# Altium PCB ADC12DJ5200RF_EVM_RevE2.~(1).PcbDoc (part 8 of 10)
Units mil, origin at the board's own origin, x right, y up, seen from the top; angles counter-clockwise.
Board outline 10500 x 2750 mil, 14 copper layers (Top Copper, Layer 2 (GND1), Layer 3 (SIG1), Layer 4 (GND2, Layer 5 (PWR1), Layer 6 (GND3), Layer 7 (PWR/SIGNAL2), Layer 8 (PWR/SIGNAL3), Layer 9 (GND4), Layer 10 PWR2), Layer 11 (GND5), Layer 12 (SIG4), Layer 13 (GND6), Bottom Copper), stack 60.6 mil thick; 701 components, 826 nets, 3386 pads, 2128 vias.

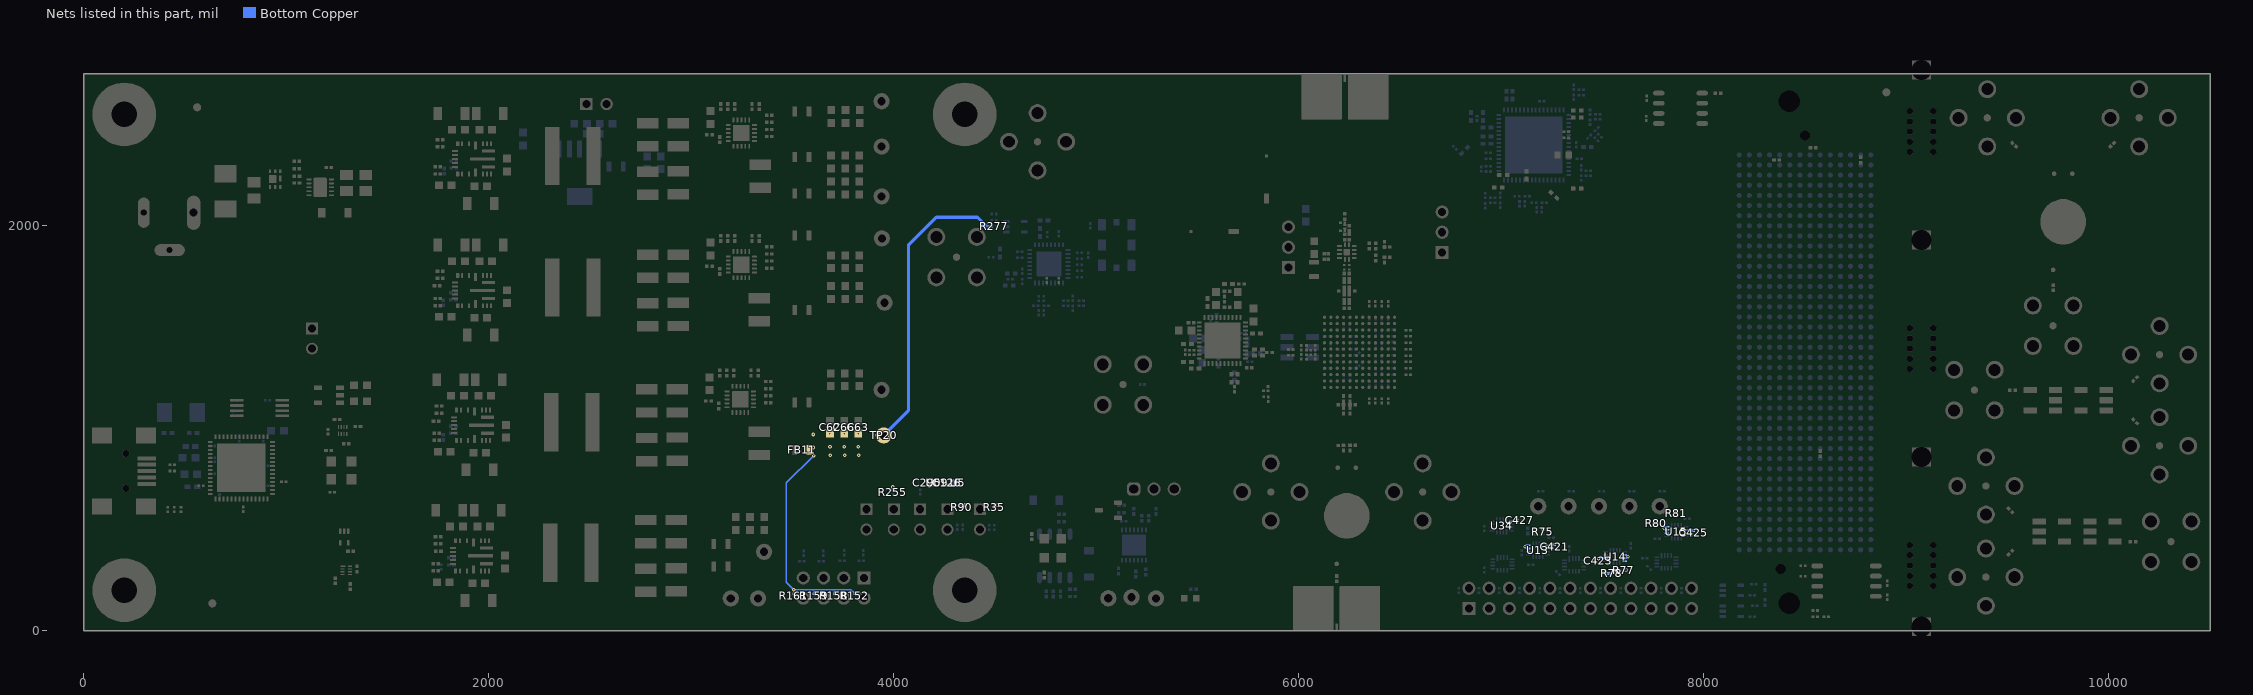
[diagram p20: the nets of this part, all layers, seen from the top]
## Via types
v1: diameter 18, hole 8, Top Copper to Bottom Copper, tented both sides, 1234 vias
v2: diameter 18, hole 8, Top Copper to Bottom Copper, tented top, 219 vias
v3: diameter 16, hole 8, Top Copper to Bottom Copper, tented both sides, 138 vias
v4: diameter 19.68, hole 7.87, Top Copper to Bottom Copper, 103 vias
v5: diameter 20, hole 10, Top Copper to Bottom Copper, tented top, 96 vias
v6: diameter 20, hole 10, Top Copper to Bottom Copper, tented both sides, 71 vias
v7: diameter 15.75/18/18/18/16/18/18/18/18/16/18/18/18/18 (per signal layer), hole 8, Top Copper to Bottom Copper, 50 vias
v8: diameter 20, hole 10, Top Copper to Bottom Copper, 40 vias
v9: diameter 15.75, hole 7.87, Top Copper to Bottom Copper, 28 vias
v10: diameter 21.81, hole 10, Top Copper to Bottom Copper, 26 vias
v11: diameter 15.75/16/16/16/16/16/16/16/16/16/16/16/16/18 (per signal layer), hole 8, Top Copper to Bottom Copper, 26 vias
v12: diameter 18, hole 8, Top Copper to Bottom Copper, tented bottom, 18 vias
v13: diameter 25.75, hole 15.75, Top Copper to Bottom Copper, 16 vias
v14: diameter 15.75/16/16/16/16/16/16/18/16/16/16/16/16/18 (per signal layer), hole 8, Top Copper to Bottom Copper, 15 vias
v15: diameter 30, hole 15, Top Copper to Bottom Copper, tented both sides, 12 vias
v16: diameter 15.75/16/16/16/18/16/16/16/16/16/16/16/16/18 (per signal layer), hole 8, Top Copper to Bottom Copper, 11 vias
v17: diameter 15.75/16/16/16/16/16/16/16/16/18/16/16/16/18 (per signal layer), hole 8, Top Copper to Bottom Copper, 7 vias
v18: diameter 15.75/16/16/16/16/16/16/18/16/18/16/16/16/18 (per signal layer), hole 8, Top Copper to Bottom Copper, 5 vias
v19: diameter 119.29, hole 77.95, Top Copper to Bottom Copper, 4 vias
v20: diameter 18, hole 8, Top Copper to Bottom Copper, 4 vias
v21: diameter 15.75/16/16/16/18/16/16/18/16/16/16/16/16/18 (per signal layer), hole 8, Top Copper to Bottom Copper, 2 vias
v22: diameter 15.75/16/16/16/16/16/18/16/16/16/16/16/16/18 (per signal layer), hole 8, Top Copper to Bottom Copper, 2 vias
v23: diameter 15.75/16/16/16/16/16/18/18/16/16/16/16/16/18 (per signal layer), hole 8, Top Copper to Bottom Copper, 1 vias

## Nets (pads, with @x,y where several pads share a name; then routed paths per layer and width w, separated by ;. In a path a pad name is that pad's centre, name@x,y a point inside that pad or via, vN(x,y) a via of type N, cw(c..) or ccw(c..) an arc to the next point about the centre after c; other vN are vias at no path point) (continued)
VDDL19: C62.1 C63.1 C66.1 C126.1 C290.1 C421.1 C423.1 C425.1 C427.1 FB11.2 R35.1 R75.1 R77.1 R78.1 R80.1 R81.1 R90.1 R152.2 R158.2 R159.2 R161.2 R255.2 R277.2 TP20.1 U5.1 U5.6 U13.5 U13.14 U13.15 U13.16 U14.6 U14.14 U14.15 U14.16 U15.6 U15.14 U15.15 U15.16 U34.13 U59.6 | length 2974.5
  Bottom Copper w7: R161.2@3506,183.05 v1(3506,203) ; v1(3605,865) 3470,730 3470,239 v1(3506,203) ; R159.2@3606,183.05 3606,202 3605,203 ; R158.2@3706,183.05 3706,202 3707,203 ; R152.2@3807,184.05 3788.05,203 3707,203 ; v3(7480,356.02) 7482.6,358.62 U14.6@7514.88,358.62 ; v3(7513,291) 7521,283 R78.1@7532.01,283 ; v1(3506,203) 3605,203 ; 3605,203 3707,203
  Bottom Copper w8: v3(7068,542) 7071,545 C427.1@7078.98,545 ; U13.14@7133.5,390.47 U13.15@7133.5,406.22 7125.78,406.22 v3(7117,415) 7123.97,421.97 U13.16@7133.5,421.97 ; v3(7246,422) 7250.02,426.02 C421.1@7265,426.02 ; U14.16@7609.37,342.87 U14.15@7609.37,358.62 7618.62,358.62 v3(7626,366) 7617.63,374.37 U14.14@7609.37,374.37 ; U15.14@7817.76,482.13 U15.15@7817.76,497.87 7812.13,497.87 v3(7805,505) 7813.62,513.62 U15.16@7817.76,513.62 ; U15.6@7912.24,497.87 7929.87,497.87 v3@7931.72,496.02
  Bottom Copper w10: v3@7931.72,496.02 C425.1@7950,496.02
  Bottom Copper w11.5: R255.2@3995,696.02 v1(3995,710) ; v1(4176,717) 4177.19,718.19 U59.6@4195.31,718.19 ; v1(4278,719) 4278.81,718.19 U5.6@4295.31,718.19 U5.1@4295.31,740.83 ; R90.1@4335,621.02 v1(4353,621) ; 4456.81,1998.19 R277.2@4483.98,1998.19 ; R35.1@4496.02,621.02 v20(4511,621)
  Bottom Copper w15: TP20.1@3950,965 4072,1087 4072,1904.02 4209.98,2042 4413,2042 4456.81,1998.19
  other v1: 3687.09,866.5 3757.09,866.5 3827.09,866.5 3603,905 3684.76,909.05 3754.76,909.05 3824.76,909.05 3602.91,969.57 3684.68,973.61 3754.68,973.61 3824.68,973.61
  other v3: 7616.02,300 7930,498 7205.98,499.41 7753.98,530 7865,591.02
pads on no net: FID1.1 FID2.1 FID3.1 FID4.1 FID5.1 FID6.1 J1. J20.10 J20.11 LBL1.0 Q2.0 Q2.0_1 U7.4A U7.4B U7.8A U7.8B U7.9A U7.9B U7.9C U7.9D U7.10A U7.10B U7.14A U7.14B U9.4A U9.4B U9.8A U9.8B U9.9A U9.9B U9.9C U9.9D U9.10A U9.10B U9.14A U9.14B U17. U23.4A U23.4B U23.8A U23.8B U23.9A U23.9B U23.9C U23.9D U23.10A U23.10B U23.14A U23.14B U43.4A U43.4B U43.8A U43.8B U43.9A U43.9B U43.9C U43.9D U43.10A U43.10B U43.14A U43.14B U51.1_1 U51.1_2 U51.2_1 U51.2_2 U51.3_1 U51.3_2 U51.4_1 U51.4_2 U51.5_1 U51.5_2 U51.6_1 U51.6_2 U52.41@5565.55,1375.9 U52.41@5565.55,1433.38 U52.41@5565.55,1490.86 U52.41@5623.03,1375.9 U52.41@5623.03,1433.38 U52.41@5623.03,1490.86 U52.41@5680.51,1375.9 U52.41@5680.51,1433.38 U52.41@5680.51,1490.86

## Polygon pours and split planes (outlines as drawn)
GND on Top Copper "GND_L01_P794" (solid, remove dead copper, pour order 794): 30,2720 8994,2720 8994,30 30,30
+3.6V on Top Copper "+3.6V_L01_P786" (solid, pour order 786): 2484,2241.09 2484,2486 2705,2486 2705,2439.4 3193,2439.4 3193,2419.79 3232,2419.79 3232,2240 2554,2240 2549,2241.09
GND on Top Copper "GND_L01_P792" (solid, pour order 792): 84 vertices, not listed, extent 1645,2037 3410,2665
GND on Top Copper "Top Copper-GND 2" (solid, pour order 755): 79 vertices, not listed, extent 6138.19,-40.71 6235.81,293.66
GND2 on Top Copper "Top Copper-GND2 17" (solid, pour order 728): 98 vertices, not listed, extent 6137.09,222.46 6236.91,380.03
GND2 on Top Copper "Top Copper-GND2 5" (solid, pour order 735): 110 vertices, not listed, extent 9489.92,1134.79 9683.69,1242.17
GND2 on Top Copper "Top Copper-GND2 6" (solid, pour order 750): 104 vertices, not listed, extent 9279.63,1131.68 9559.1,1245.28
GND2 on Top Copper "Top Copper-GND2 7" (solid, pour order 744): 105 vertices, not listed, extent 9336.33,208.2 9555.53,427.41
GND2 on Top Copper "Top Copper-GND2 8" (solid, pour order 743): 105 vertices, not listed, extent 9336.33,552.59 9555.53,771.8
GND2 on Top Copper "Top Copper-GND2 9" (solid, pour order 772): 288 vertices, not listed, extent 9467.2,426.02 9977.69,635.78
GND2 on Top Copper "Top Copper-GND2 10" (solid, pour order 770): 229 vertices, not listed, extent 9472.35,294.25 9977.69,493.69
GND2 on Top Copper "Top Copper-GND2 11" (solid, pour order 736): 110 vertices, not listed, extent 9960.31,386.31 10154.08,493.69
GND2 on Top Copper "Top Copper-GND2 12" (solid, pour order 749): 104 vertices, not listed, extent 10084.9,383.2 10364.37,496.8
GND2 on Top Copper "Top Copper-GND2 13" (solid, pour order 741): 105 vertices, not listed, extent 10088.47,856.68 10307.67,1075.89
GND2 on Top Copper "Top Copper-GND2 14" (solid, pour order 767): 196 vertices, not listed, extent 9666.31,992.71 10171.65,1142.17
GND2 on Top Copper "Top Copper-GND2 15" (solid, pour order 766): 163 vertices, not listed, extent 9666.31,1134.79 10171.65,1284.26
GND2 on Top Copper "Top Copper-GND2 16" (solid, pour order 742): 105 vertices, not listed, extent 10088.47,1201.08 10307.67,1420.28
GND2 on Top Copper "GND2_L01_P793" (solid, remove dead copper, pour order 793): 10500,2750 9157,2750 9157,0 10500,0
GND2 on Top Copper "Top Copper-GND 1" (solid, pour order 746): 102 vertices, not listed, extent 9670.5,145.41 9779.5,422.58
GND2 on Top Copper "Top Copper-GND2" (solid, pour order 748): 103 vertices, not listed, extent 9345.5,2358.45 9574.52,2587.47
GND2 on Top Copper "Top Copper-GND2 1" (solid, pour order 747): 103 vertices, not listed, extent 9975.48,2358.45 10204.5,2587.47
GND2 on Top Copper "Top Copper-GND2 2" (solid, pour order 756): 146 vertices, not listed, extent 9766.47,2205.95 10058.66,2441.63
GND2 on Top Copper "Top Copper-GND2 3" (solid, pour order 757): 147 vertices, not listed, extent 9491.34,2205.95 9783.53,2441.63
GND2 on Top Copper "Top Copper-GND2 4" (solid, pour order 745): 102 vertices, not listed, extent 9670.5,1451.41 9779.5,1728.58
no net on Top Copper "NONET_L01_P718" (solid, remove dead copper, pour order 718): 8994.2,2043.1
GND on Top Copper "Top Copper-GND 11" (solid, pour order 761): 79 vertices, not listed, extent 6190.52,2021.1 6263.94,2773.61
GND on Top Copper "Top Copper-GND" (solid, pour order 737): 106 vertices, not listed, extent 6201.62,2020.46 6296.53,2267.53
GND on Top Copper "Top Copper-GND 5" (solid, pour order 734): 122 vertices, not listed, extent 6204.19,753.03 6333.92,939.64
GND on Top Copper "Top Copper-GND 6" (solid, pour order 733): 126 vertices, not listed, extent 6140.08,753.03 6269.81,939.64
GND on Top Copper "Top Copper-GND 7" (solid, pour order 740): 41 vertices, not listed, extent 6171.4,866.21 6270.6,1122.61
GND on Top Copper "Top Copper-GND 8" (solid, pour order 739): 45 vertices, not listed, extent 6203.37,866.42 6302.58,1122.61
GND on Top Copper "Top Copper-GND 9" (solid, pour order 759): 135 vertices, not listed, extent 6229.36,628.48 6668.52,964.81
GND on Top Copper "Top Copper-GND 10" (solid, pour order 758): 133 vertices, not listed, extent 5805.48,628.48 6244.62,963.84
NetC94_1 on Top Copper "NETC94_1_L01_P724" (solid, remove dead copper, pour order 724): 6300,1850.93 6360,1850.93 6360,1839.93 6361,1840.93 6398,1840.93 6398,1831.93 6451,1831.93 6451,1884.93 6398,1884.93 6398,1881.93 6397,1881.93 6360,1881.93 6360,1868.93 6300,1868.93
GND on Top Copper "Top Copper-GND 3" (solid, pour order 725): 149 vertices, not listed, extent 6174.78,1501.67 6299.23,1594.79
VD11 on Top Copper "VD11_L01_P769" (solid, pour order 769): 3171,520 3380,520 3410,520 3425,505 3430,500 3430,380 3430,305 3413,288 3171.02,288
GND on Top Copper "GND_L01_P791" (solid, pour order 791): 86 vertices, not listed, extent 1645,1387 3410,2015
GND on Top Copper "GND_L01_P790" (solid, pour order 790): 88 vertices, not listed, extent 1640,722 3405,1350
GND on Top Copper "GND_L01_P789" (solid, pour order 789): 62 vertices, not listed, extent 1635,77 2981,705
+1.4V on Top Copper "+1.4V_L01_P787" (solid, pour order 787): 2484,1591.09 2484,1838 2705,1838 2705,1789.4 3193,1789.4 3193,1769.79 3232,1769.79 3232,1590 2554,1590 2549,1591.09
+2.2V on Top Copper "+2.2V_L01_P788" (solid, pour order 788): 2479,910.86 2479,1171 2701.73,1171 2701.73,1109.17 3229,1109.17 3229,909.77 2550.73,909.77 2545.73,910.86
NetC107_1 on Top Copper "NETC107_1_L01_P719" (solid, remove dead copper, pour order 719): 6232,1896
3p3VAMP on Top Copper "3P3VAMP_L01_P777" (solid, pour order 777): 4001.77,1830 4001.77,1980 3571,1980 3571,1830
NetC208_2 on Top Copper "NETC208_2_L01_P765" (solid, pour order 765): 27 vertices, not listed, extent 1902,2211 2304,2463
NetC129_2 on Top Copper "NETC129_2_L01_P762" (solid, pour order 762): 27 vertices, not listed, extent 1902,1561 2304,1813
NetC165_2 on Top Copper "NETC165_2_L01_P764" (solid, pour order 764): 27 vertices, not listed, extent 1897,896 2299,1148
NetC67_2 on Top Copper "NETC67_2_L01_P763" (solid, pour order 763): 27 vertices, not listed, extent 1892,251 2294,503
+7V on Top Copper "+7V_L01_P729" (solid, pour order 729): 1840,2150 1840,2072.6 1955,2072.6 1955,2285 1920,2285 1920,2222.27 1898.98,2222.27 1898.98,2150
+7V on Top Copper "+7V_L01_P732" (solid, pour order 732): 1840,1500 1840,1422.6 1955,1422.6 1955,1635 1920,1635 1920,1572.27 1898.98,1572.27 1898.98,1500
+7V on Top Copper "+7V_L01_P731" (solid, pour order 731): 1835,835 1835,757.6 1950,757.6 1950,970 1915,970 1915,907.27 1893.98,907.27 1893.98,835
+7V on Top Copper "+7V_L01_P730" (solid, pour order 730): 1830,190 1830,112.6 1945,112.6 1945,325 1910,325 1910,262.27 1888.98,262.27 1888.98,190
+7V on Top Copper "+7V_L01_P751" (solid, pour order 751): 18 vertices, not listed, extent 1835,2375 1980,2625
+7V on Top Copper "+7V_L01_P752" (solid, pour order 752): 18 vertices, not listed, extent 1835,1725 1980,1975
+7V on Top Copper "+7V_L01_P754" (solid, pour order 754): 18 vertices, not listed, extent 1830,1060 1975,1310
+7V on Top Copper "+7V_L01_P753" (solid, pour order 753): 18 vertices, not listed, extent 1825,415 1970,665
GND on Top Copper "GND_L01_P717" (solid, remove dead copper, pour order 717): 5942.85,933.69
VA11 on Top Copper "VA11_L01_P776" (solid, pour order 776): 4000,1510 4000,1660 3571,1660 3571,1510
NetC164_1 on Top Copper "NETC164_1_L01_P760" (solid, pour order 760): 3390,1840 3429.19,1840 3438.19,1831 3521,1831 3521,1559 3430,1559 3430,1625 3265,1625 3265,1760 3295,1760 3295,1771.58 3390,1771.58
+3.3VCLK on Top Copper "+3.3VCLK_L01_P774" (solid, pour order 774): 3571,2690 3571,2540 3995,2540 3995,2690
VA19 on Top Copper "VA19_L01_P768" (solid, pour order 768): 3993.66,1100 3993.66,1240 3571,1240 3571,1100
VDDD33 on Top Copper "VDDD33_L01_P775" (solid, pour order 775): 3571,2465 3571,2315 3995,2315 3995,2465
VDDL19 on Top Copper "VDDL19_L01_P771" (solid, pour order 771): 3991.77,855 3991.77,1005 3571,1005 3571,855
3.3V-LMX on Top Copper "3.3V-LMX_L01_P778" (solid, pour order 778): 4001.77,2035 4001.77,2185 3571,2185 3571,2035
NetC101_1 on Top Copper "NETC101_1_L01_P783" (solid, pour order 783): 2544,280 3121,280 3121,479.4 2695,479.4 2695,529 2476,529 2476,281.09 2539,281.09
NetC7_1 on Top Copper "NETC7_1_L01_P781" (solid, pour order 781): 19 vertices, not listed, extent 3265,1928.02 3521,2688.02
NetC200_1 on Top Copper "NETC200_1_L01_P773" (solid, pour order 773): 3425,910 3425,869 3521,869 3521,1260 3433.19,1260 3433.19,1175 3385,1175 3385,1106.58 3290,1106.58 3290,1095 3260,1095 3260,960 3425,960
NetC310_1 on Top Copper "NETC310_1_L01_P780" (solid, pour order 780): 27 vertices, not listed, extent 4684,1661 5002,2011
GND on Top Copper "GND_L01_P727" (solid, pour order 727): 17 vertices, not listed, extent 4704,1734 4828,1826
NetC55_2 on Top Copper "NETC55_2_L01_P726" (solid, pour order 726): 20 vertices, not listed, extent 6985.12,2170.15 7160,2244
NetC235_2 on Top Copper "NETC235_2_L01_P784" (solid, pour order 784): 239,1969 397,1969 397,2123 397,2190 871,2190 909,2190 909,2184 909,2182 949,2182 952,2182 952,2202 952,2356 654,2356 239,2356 239,2284
NetC116_2 on Top Copper "NETC116_2_L01_P722" (solid, pour order 722): 1845,305 1845,277.52 1836.02,268.54 1834.98,267.5 1834.98,245 1834.98,229.98 1825,220 1785,220 1785,270 1825,310 1840,310
NetC193_2 on Top Copper "NETC193_2_L01_P723" (solid, pour order 723): 1850,950 1850,922.52 1841.02,913.54 1839.98,912.5 1839.98,890 1839.98,874.98 1830,865 1790,865 1790,915 1830,955 1845,955
NetC137_2 on Top Copper "NETC137_2_L01_P721" (solid, pour order 721): 1855,1615 1855,1587.52 1846.02,1578.54 1844.98,1577.5 1844.98,1555 1844.98,1539.98 1835,1530 1795,1530 1795,1580 1835,1620 1850,1620
NetC235_1 on Top Copper "NETC235_1_L01_P785" (solid, pour order 785): 20 vertices, not listed, extent 495,1929.75 1125,2226.5
+7V on Top Copper "+7V_L01_P782" (solid, pour order 782): 1212.31,2196 1600,2196 1600,2106.59 1600,1920 1343.29,1920 1211,1920 1211,2151.94
GND on Top Copper "GND_L01_P779" (solid, pour order 779): 19 vertices, not listed, extent 1135,2035 1485,2405
GND on Top Copper "GND_L01_P738" (solid, pour order 738): 1970,2300 2050,2300 2050,2295 2050,2045 2045,2045 1975,2045 1975,2055 1975,2045 1970,2045 1970,2220 1970,2240 1965,2240 1965,2280 1965,2300
NetC221_2 on Top Copper "NETC221_2_L01_P720" (solid, pour order 720): 1855,2265 1855,2237.52 1846.02,2228.54 1844.98,2227.5 1844.98,2205 1844.98,2189.98 1835,2180 1795,2180 1795,2230 1835,2270 1850,2270
GND on Bottom Copper "GND_L14_P846" (solid, remove dead copper, pour order 846): 30,2720 8970,2720 8970,30 30,30
FE_VDD on Bottom Copper "Bottom Copper-FE_VDD" (solid, remove dead copper, pour order 841): 2654.64,2268.42 2736,2268.42 2736,2318.02 3212,2318.02 3212,2373.02 2734.98,2373.02 2654.64,2373.02
+7V on Bottom Copper "Bottom Copper-+7V" (solid, remove dead copper, pour order 842): 2144.01,2228.02 2324.01,2228.02 2336,2228.02 2336,2339.67 2409,2339.67 2409,2421 2144.01,2421
NetFB4_1 on Bottom Copper "NETFB4_1_L14_P839" (solid, remove dead copper, pour order 839): 2486.19,2418.33 2509.81,2418.33 2509.81,2317.81 2509.04,2317.04 2604.8,2317.04 2604.8,2269.01 2604.8,2269 2486,2269
GND2 on Bottom Copper "GND2_L14_P845" (solid, remove dead copper, pour order 845): 10500,2750 9157,2750 9157,0 10500,0
GND on Bottom Copper "GND_L14_P844" (solid, remove dead copper, pour order 844): 5346.14,1971.69 5558.27,1759.56 5982.54,2183.82 5982.54,2325.24 5841.12,2466.66
NetC58_1 on Bottom Copper "NETC58_1_L14_P840" (solid, pour order 840): 6830,2499 6830,2430.07 6883.07,2377 6922,2377 6923,2378 6925.84,2380.84 6925.84,2534.65 6923.49,2537 6834.28,2537 6834.16,2536.87 6830,2532.72
NetC235_1 on Bottom Copper "NETC235_1_L14_P843" (solid, pour order 843): 509,2160 509,2161 1039,2161 1121,2161 1121,1953 1121,1884.61 558,1884.61 540,1884.61 540,1930 540,1945 487,1945 487,2057 487,2113 487,2160
VDDD33 on Layer 5 (PWR1) "VDDD33_L05_P812" (solid, remove dead copper, pour order 812): 40,2710 40,40 2680,40 2680,2020 6304,2020 6304,1650 7850,1650 7850,740 7040,740 6780,480 6780,40 8960,40 8960,2710
VD11 on Layer 5 (PWR1) "VD11_L05_P811" (solid, remove dead copper, pour order 811): 2720,40 6740,40 6740,500 7010,780 7810,780 7810,1620 6301,1620 6301,1020 2720,1020
GND2 on Layer 5 (PWR1) "GND2_L05_P810" (solid, remove dead copper, pour order 810): 10500,2750 9157,2750 9157,0 10500,0
VA11 on Layer 5 (PWR1) "VA11_L05_P809" (solid, remove dead copper, pour order 809): 6270,1060 2720,1060 2720,1980 6270,1980
+3.3VA on Layer 3 (SIG1) "+3.3VA_L03_P805" (solid, remove dead copper, pour order 805): 30,30 30,2720 3540,2720 3540,2320 3540,30
GND on Layer 3 (SIG1) "GND_L03_P806" (solid, remove dead copper, pour order 806): 3590,2720 3590,30 8970,30 8970,2720
GND2 on Layer 3 (SIG1) "GND2_L03_P804" (solid, remove dead copper, pour order 804): 10500,2750 9157,2750 9157,0 10500,0
NetC317_1 on Layer 3 (SIG1) "NETC317_1_L03_P803" (solid, pour order 803): 21 vertices, not listed, extent 4568,1661 5008,1943
+7V on Layer 7 (PWR/SIGNAL2) "+7V_L07_P801" (solid, remove dead copper, pour order 801): 40,2710 3480,2710 3480,1980 3480,960 3240,960 2980,960 2980,280 2980,40 40,40
GND on Layer 7 (PWR/SIGNAL2) "GND_L07_P802" (solid, remove dead copper, pour order 802): 8200,2710 8970,2710 8970,40 3040,40 3040,680 3040,920 3280,920 3520,920 3520,1080 3520,1620 4420,1620 5160,1620 8200,1620 8200,2100
+3.3VCLK on Layer 7 (PWR/SIGNAL2) "+3.3VCLK_L07_P800" (solid, remove dead copper, pour order 800): 3520,2710 3520,1660 8160,1660 8160,2710
GND2 on Layer 7 (PWR/SIGNAL2) "GND2_L07_P799" (solid, remove dead copper, pour order 799): 10500,2750 9157,2750 9157,0 10500,0
GND on Layer 7 (PWR/SIGNAL2) "GND_L07_P798" (solid, remove dead copper, pour order 798): 5346.14,1971.69 5558.27,1759.56 5982.54,2183.82 5982.54,2325.24 5841.12,2466.66
VDD18-USB on Layer 7 (PWR/SIGNAL2) "VDD18-USB_L07_P797" (solid, remove dead copper, pour order 797): 550,1025 1025,1025 1025,600 550,600
+7V on Layer 10 PWR2) "+7V_L10_P829" (solid, pour order 829): 40,2710 3480,2710 3480,40 40,40
VDDL19 on Layer 10 PWR2) "VDDL19_L10_P826" (solid, pour order 826): 3550,1060 4760,1060 4760,710 8060,710 8060,40 3550,40
3p3VAMP on Layer 10 PWR2) "3P3VAMP_L10_P825" (solid, remove dead copper, pour order 825): 3547,2720 3547,1797 6838,1797 6838,2720
GND2 on Layer 10 PWR2) "GND2_L10_P827" (solid, remove dead copper, pour order 827): 10500,2750 9157,2750 9157,0 10500,0
VA19 on Layer 10 PWR2) "VA19_L10_P824" (solid, remove dead copper, pour order 824): 4800,1100 4800,750 6840,750 6840,1414.95 6840,1740 3550.9,1740 3550.9,1414.95 3550,1414.95 3550,1100 3550.9,1100
GND on Layer 10 PWR2) "GND_L10_P828" (solid, pour order 828): 7540,1900 7540,2710 7750,2710 8970,2710 8970,40 8100,40 8100,750 6880,750 6880,1900
NetC47_1 on Layer 10 PWR2) "NETC47_1_L10_P823" (solid, pour order 823): 6880,2710 7500,2710 7500,1940 6880,1940
GND on Layer 8 (PWR/SIGNAL3) "GND_L08_P820" (solid, remove dead copper, pour order 820): 30,2720 8970,2720 8970,30 30,30
GND on Layer 8 (PWR/SIGNAL3) "GND_L08_P819" (solid, remove dead copper, pour order 819): 40,2710 4020,2710 4020,40 540,40 40,40 40,1720 380,1720 1200,1720 1200,1880 1200,2180 840,2180 40,2180
VDDD33 on Layer 8 (PWR/SIGNAL3) "VDDD33_L08_P817" (solid, remove dead copper, pour order 817): 4060,40 4060,570 5050,570 6790,570 6880,480 7320,480 7400,480 7440,440 7460,420 7460,300 7460,60 7440,40 6920,40
GND2 on Layer 8 (PWR/SIGNAL3) "GND2_L08_P818" (solid, remove dead copper, pour order 818): 10500,2750 9157,2750 9157,0 10500,0
NetC235_1 on Layer 8 (PWR/SIGNAL3) "NETC235_1_L08_P816" (solid, remove dead copper, pour order 816): 478.4,2159.14 479.69,2157.85 949.4,2157.85 1012.62,2157.85 1136.5,2033.97 1135.21,2032.68 1135.21,1908.8 1135.21,1882.99 1115.86,1863.64 1114.57,1862.35 655.19,1862.35 604.85,1862.35 496.46,1970.74 478.4,1988.8 478.4,2040.42
GND on Layer 12 (SIG4) "GND_L12_P836" (solid, pour order 836): 30,2718.69 8970,2718.69 8970,28.69 30,28.69
FE_VDD on Layer 12 (SIG4) "FE_VDD_L12_P833" (solid, pour order 833): 2890,2717.69 2890,2156.72 2895.85,2150.87 2906.91,2161.93 5940,2161.93 5940,1671.93 6750,1671.93 6750,2717.69 4512.85,2717.69
GND2 on Layer 12 (SIG4) "GND2_L12_P835" (solid, remove dead copper, pour order 835): 10500,2750 9157,2750 9157,0 10500,0
3.3V-LMX on Layer 12 (SIG4) "3.3V-LMX_L12_P834" (solid, pour order 834): 5803,2132 5921,2014 5921,1038 5605,722 3739,722 3581,880 3581,2085 3577,2089 3599,2118 3611,2130 3611,2132
no net on Layer 12 (SIG4) "NONET_L12_P832" (solid, remove dead copper, pour order 832): 2910,2721.93
no net on Layer 6 (GND3) "NONET_L06_P815" (solid, pour order 815): 30,2720 8860,2720 8970,2720 8970,30 30,30
GND on Layer 6 (GND3) "GND_L06_P814" (solid, pour order 814): 30,2720 8860,2720 8970,2720 8970,30 30,30
GND2 on Layer 6 (GND3) "GND2_L06_P813" (solid, remove dead copper, pour order 813): 10500,2750 9157,2750 9157,0 10500,0
GND on Layer 4 (GND2 "GND_L04_P808" (solid, remove dead copper, pour order 808): 30,2720 8970,2720 8970,30 30,30
GND2 on Layer 4 (GND2 "GND2_L04_P807" (solid, remove dead copper, pour order 807): 10500,2750 9157,2750 9157,0 10500,0
GND on Layer 9 (GND4) "GND_L09_P822" (solid, pour order 822): 8970,30 8970,2720 30,2720 30,30
GND2 on Layer 9 (GND4) "GND2_L09_P821" (solid, remove dead copper, pour order 821): 10500,2750 9157,2750 9157,0 10500,0
GND on Layer 11 (GND5) "GND_L11_P831" (solid, remove dead copper, pour order 831): 30,2720 8970,2720 8970,30 30,30
GND2 on Layer 11 (GND5) "GND2_L11_P830" (solid, remove dead copper, pour order 830): 10500,2750 9157,2750 9157,0 10500,0
GND on Layer 13 (GND6) "GND_L13_P838" (solid, pour order 838): 30,2720 8970,2720 8970,30 30,30
GND2 on Layer 13 (GND6) "GND2_L13_P837" (solid, remove dead copper, pour order 837): 10500,2750 9157,2750 9157,0 10500,0
GND on Layer 2 (GND1) "GND_L02_P796" (solid, remove dead copper, pour order 796): 30,2720 8993,2720 8993,30 30,30
GND2 on Layer 2 (GND1) "GND2_L02_P795" (solid, remove dead copper, pour order 795): 10500,2750 9157,2750 9157,0 10500,0

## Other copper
Top Copper:
  drawing of 126 lines, arcs and shapes, not listed
  text ".Layer_Name" at 576,-857 h60
Layer 2 (GND1):
  pour cut-out: 9802,2259.44 9802,2272.44 9838,2272.44 9838,2259.44 cw(c9820,2259.44) 9820,2241.44 cw(c9820,2259.44)
  pour cut-out: 9712,2259.44 9712,2272.44 9748,2272.44 9748,2259.44 cw(c9730,2259.44) 9730,2241.44 cw(c9730,2259.44)
  pour cut-out: 9743,1779.52 9743,1766.52 9707,1766.52 9707,1779.52 cw(c9725,1779.52) 9725,1797.52 cw(c9725,1779.52)
  pour cut-out: 10307.48,414 ccw(c10307.48,440) 10333.48,440 ccw(c10307.48,440) 10307.48,466 ccw(c10307.48,440) 10281.48,440 ccw(c10307.48,440)
  pour cut-out: 9393.13,689 ccw(c9393.13,715) 9419.13,715 ccw(c9393.13,715) 9393.13,741 ccw(c9393.13,715) 9367.13,715 ccw(c9393.13,715)
  pour cut-out: 9393.13,238.65 ccw(c9393.13,264.65) 9419.13,264.65 ccw(c9393.13,264.65) 9393.13,290.65 ccw(c9393.13,264.65) 9367.13,264.65 ccw(c9393.13,264.65)
  pour cut-out: 10124,2532.97 ccw(c10150,2532.97) 10150,2506.97 ccw(c10150,2532.97) 10176,2532.97 ccw(c10150,2532.97) 10150,2558.97 ccw(c10150,2532.97)
  pour cut-out: 9374,2532.97 ccw(c9400,2532.97) 9400,2506.97 ccw(c9400,2532.97) 9426,2532.97 ccw(c9400,2532.97) 9400,2558.97 ccw(c9400,2532.97)
  pour cut-out: 9699,1506 ccw(c9725,1506) 9725,1480 ccw(c9725,1506) 9751,1506 ccw(c9725,1506) 9725,1532 ccw(c9725,1506)
  pour cut-out: 10250.87,1389.83 ccw(c10250.87,1363.83) 10224.87,1363.83 ccw(c10250.87,1363.83) 10250.87,1337.83 ccw(c10250.87,1363.83) 10276.87,1363.83 ccw(c10250.87,1363.83)
  pour cut-out: 10250.87,939.48 ccw(c10250.87,913.48) 10224.87,913.48 ccw(c10250.87,913.48) 10250.87,887.48 ccw(c10250.87,913.48) 10276.87,913.48 ccw(c10250.87,913.48)
  pour cut-out: 9336.52,1214.48 ccw(c9336.52,1188.48) 9310.52,1188.48 ccw(c9336.52,1188.48) 9336.52,1162.48 ccw(c9336.52,1188.48) 9362.52,1188.48 ccw(c9336.52,1188.48)
  pour cut-out: 6205,327.58 6205,314.58 6169,314.58 6169,327.58 cw(c6187,327.58) 6187,345.58 cw(c6187,327.58)
  pour cut-out: 6174,807.5 6174,820.5 6210,820.5 6210,807.5 cw(c6192,807.5) 6192,789.5 cw(c6192,807.5)
  pour cut-out: 6264,807.5 6264,820.5 6300,820.5 6300,807.5 cw(c6282,807.5) 6282,789.5 cw(c6282,807.5)
  pour cut-out: 5836,685 ccw(c5862,685) 5862,659 ccw(c5862,685) 5888,685 ccw(c5862,685) 5862,711 ccw(c5862,685)
  pour cut-out: 6586,685 ccw(c6612,685) 6612,659 ccw(c6612,685) 6638,685 ccw(c6612,685) 6612,711 ccw(c6612,685)
  pour cut-out: 4992.97,1633.82 4992.97,1602.82 4993,1602.82 ccw(c5016,1603) 5038.98,1602.05 5038.99,1602.03 5038.99,1633.03 5038.96,1633.02 ccw(c5015.96,1632.86)
  pour cut-out: 7646.67,2469.24 7624.75,2447.32 7624.77,2447.3 ccw(c7641.16,2431.16) 7656.74,2414.24 7656.73,2414.21 7678.65,2436.14 7678.62,2436.15 ccw(c7662.24,2452.3)
  pour cut-out: 7515.35,2421.08 7493.43,2399.16 7493.45,2399.14 ccw(c7509.84,2383) 7525.41,2366.08 7525.4,2366.06 7547.33,2387.98 7547.3,2388 ccw(c7530.92,2404.15)
  pour cut-out: 6887.61,2265.5 6887.61,2296.5 6887.58,2296.49 ccw(c6864.58,2296.32) 6841.6,2297.27 6841.59,2297.29 6841.59,2266.29 6841.62,2266.29 ccw(c6864.62,2266.46)
  pour cut-out: 7171.21,1996.48 7202.21,1996.48 7202.2,1996.51 ccw(c7202.03,2019.51) 7202.98,2042.49 7203,2042.5 7172,2042.5 7172,2042.47 ccw(c7172.17,2019.47)
  pour cut-out: 4744.23,1540.65 4713.23,1540.65 4713.23,1540.62 ccw(c4713.41,1517.62) 4712.46,1494.64 4712.44,1494.63 4743.44,1494.63 4743.43,1494.66 ccw(c4743.27,1517.67)
  pour cut-out: 7525.54,2366.14 7547.46,2388.06 7547.44,2388.08 ccw(c7531.05,2404.22) 7515.47,2421.14 7515.48,2421.16 7493.56,2399.24 7493.58,2399.22 ccw(c7509.97,2383.07)
  pour cut-out: 7656.86,2414.3 7678.78,2436.22 7678.76,2436.23 ccw(c7662.37,2452.37) 7646.8,2469.3 7646.8,2469.32 7624.88,2447.4 7624.91,2447.38 ccw(c7641.29,2431.23)
  pour cut-out: 7466.4,2274.28 7466.4,2243.28 7466.43,2243.28 ccw(c7489.42,2243.46) 7512.41,2242.5 7512.41,2242.48 7512.41,2273.48 7512.39,2273.48 ccw(c7489.38,2273.31)
  pour cut-out: 7127.03,2644.75 7127.03,2675.75 7127,2675.74 ccw(c7104,2675.57) 7081.02,2676.52 7081.01,2676.54 7081.01,2645.54 7081.04,2645.54 ccw(c7104.04,2645.71)
  pour cut-out: 7436.16,2581.64 7467.16,2581.64 7467.16,2581.67 ccw(c7466.98,2604.67) 7467.93,2627.65 7467.95,2627.66 7436.95,2627.66 7436.96,2627.63 ccw(c7437.12,2604.63)
  pour cut-out: 7223.3,2622.8 7254.3,2622.8 7254.3,2622.83 ccw(c7254.12,2645.83) 7255.07,2668.81 7255.09,2668.82 7224.09,2668.82 7224.1,2668.79 ccw(c7224.26,2645.79)
  pour cut-out: 7086.61,1908.38 7117.61,1908.38 7117.61,1908.41 ccw(c7117.43,1931.41) 7118.39,1954.39 7118.41,1954.4 7087.41,1954.4 7087.41,1954.37 ccw(c7087.58,1931.37)
  pour cut-out: 5762.2,2254.55 ccw(c5840.92,2254.55) 5840.92,2175.83 ccw(c5840.92,2254.55) 5919.64,2254.55 ccw(c5840.92,2254.55) 5840.92,2333.27 ccw(c5840.92,2254.55)
  pour cut-out: 5558.25,1892.77 ccw(c5558.25,1971.49) 5636.97,1971.49 ccw(c5558.25,1971.49) 5558.25,2050.21 ccw(c5558.25,1971.49) 5479.53,1971.49 ccw(c5558.25,1971.49)
  pour cut-out: 6126.77,1475.22 ccw(c6126.77,1485.24) 6136.79,1485.24 ccw(c6126.77,1485.24) 6136.67,1486.77 6136.67,1515.2 ccw(c6126.77,1516.73) 6136.79,1516.73 ccw(c6126.77,1516.73) 6126.77,1526.75 ccw(c6126.77,1516.73) 6116.76,1516.73 ccw(c6126.77,1516.73) 6116.9,1515.05 6116.9,1486.91 ccw(c6126.77,1485.24) 6116.76,1485.24 ccw(c6126.77,1485.24)
  pour cut-out: 6126.77,1349.24 ccw(c6126.77,1359.25) 6136.79,1359.25 ccw(c6126.77,1359.25) 6136.67,1360.79 6136.67,1389.21 ccw(c6126.77,1390.75) 6136.79,1390.75 ccw(c6126.77,1390.75) 6126.77,1400.76 ccw(c6126.77,1390.75) 6116.76,1390.75 ccw(c6126.77,1390.75) 6116.9,1389.07 6116.9,1360.93 ccw(c6126.77,1359.25) 6116.76,1359.25 ccw(c6126.77,1359.25)
  pour cut-out: 6126.77,1223.25 ccw(c6126.77,1233.27) 6136.79,1233.27 ccw(c6126.77,1233.27) 6136.67,1234.8 6136.67,1263.23 ccw(c6126.77,1264.76) 6136.79,1264.76 ccw(c6126.77,1264.76) 6126.77,1274.78 ccw(c6126.77,1264.76) 6116.76,1264.76 ccw(c6126.77,1264.76) 6116.9,1263.09 6116.9,1234.95 ccw(c6126.77,1233.27) 6116.76,1233.27 ccw(c6126.77,1233.27)
  pour cut-out: 7699.03,2614.18 7699.03,2645.18 7699,2645.18 ccw(c7676,2645) 7653.02,2645.95 7653.01,2645.97 7653.01,2614.97 7653.04,2614.98 ccw(c7676.04,2615.14)
  pour cut-out: 6211.24,1201.77 ccw(c6221.26,1201.77) 6221.26,1191.76 ccw(c6221.26,1201.77) 6222.8,1191.88 6251.22,1191.88 ccw(c6252.76,1201.77) 6252.76,1191.76 ccw(c6252.76,1201.77) 6262.77,1201.77 ccw(c6252.76,1201.77) 6252.76,1211.79 ccw(c6252.76,1201.77) 6251.08,1211.64 6222.94,1211.64 ccw(c6221.26,1201.77) 6221.26,1211.79 ccw(c6221.26,1201.77)
  pour cut-out: 6211.24,1548.23 ccw(c6221.26,1548.23) 6221.26,1538.21 ccw(c6221.26,1548.23) 6222.8,1538.33 6251.22,1538.33 ccw(c6252.76,1548.23) 6252.76,1538.21 ccw(c6252.76,1548.23) 6262.77,1548.23 ccw(c6252.76,1548.23) 6252.76,1558.24 ccw(c6252.76,1548.23) 6251.08,1558.1 6222.94,1558.1 ccw(c6221.26,1548.23) 6221.26,1558.24 ccw(c6221.26,1548.23)
  pour cut-out: 6345,1535.9 6380,1535.9 6380.02,1535.88 ccw(c6377.76,1548.17) 6379.99,1560.47 6380,1560.5 6345,1560.5 6344.98,1560.52 ccw(c6347.24,1548.21)
  pour cut-out: 6407.99,1535.9 6442.99,1535.9 6443.01,1535.88 ccw(c6440.75,1548.17) 6442.99,1560.47 6442.99,1560.5 6407.99,1560.5 6407.97,1560.52 ccw(c6410.24,1548.21)
  pour cut-out: 6345,1189.44 6380,1189.44 6380.02,1189.42 ccw(c6377.76,1201.72) 6379.99,1214.01 6380,1214.04 6345,1214.04 6344.98,1214.06 ccw(c6347.24,1201.76)
  pour cut-out: 6407.99,1189.44 6442.99,1189.44 6443.01,1189.42 ccw(c6440.75,1201.72) 6442.99,1214.01 6442.99,1214.04 6407.99,1214.04 6407.97,1214.06 ccw(c6410.24,1201.76)
  pour cut-out: 6485.56,1451.5 6485.56,1486.5 6485.58,1486.52 ccw(c6473.28,1484.25) 6460.99,1486.49 6460.96,1486.5 6460.96,1451.5 6460.94,1451.47 ccw(c6473.24,1453.74)
  pour cut-out: 6485.56,1388.5 6485.56,1423.5 6485.58,1423.53 ccw(c6473.28,1421.26) 6460.99,1423.5 6460.96,1423.5 6460.96,1388.5 6460.94,1388.48 ccw(c6473.24,1390.75)
  pour cut-out: 6485.56,1325.51 6485.56,1360.51 6485.58,1360.53 ccw(c6473.28,1358.27) 6460.99,1360.51 6460.96,1360.51 6460.96,1325.51 6460.94,1325.49 ccw(c6473.24,1327.76)
  pour cut-out: 6485.56,1262.52 6485.56,1297.52 6485.58,1297.54 ccw(c6473.28,1295.28) 6460.99,1297.51 6460.96,1297.52 6460.96,1262.52 6460.94,1262.5 ccw(c6473.24,1264.76)
  pour cut-out: 9764.65,2269.34
  pour cut-out: 9505.12,587.07 9521.06,602.63 9504.2,619.87 9488.53,604.2
  pour cut-out: 9523.49,568.7 9539.43,584.25 9522.57,601.5 9506.9,585.82
  pour cut-out: 9539.43,395.37 9523.87,411.3 9506.63,394.45 9522.3,378.78
  pour cut-out: 9521.06,376.99 9505.5,392.93 9488.26,376.07 9503.93,360.4
  pour cut-out: 10120.7,451.27 10120.43,429 10144.54,428.73 10144.54,450.89
  pour cut-out: 10094.71,451.27 10094.44,429 10118.56,428.73 10118.56,450.89
  pour cut-out: 10069,420 10069,460 9994,460 9994,420
  pour cut-out: 9944,520 9944,560 9869,560 9869,520
  pour cut-out: 9944,420 9944,460 9869,460 9869,420
  pour cut-out: 9819,420 9819,460 9744,460 9744,420
  pour cut-out: 9694,520 9694,560 9619,560 9619,520
  pour cut-out: 9950,1108.48 9950,1068.48 10025,1068.48 10025,1108.48
  pour cut-out: 9825,1208.48 9825,1168.48 9900,1168.48 9900,1208.48
  pour cut-out: 9700,1208.48 9700,1168.48 9775,1168.48 9775,1208.48
  pour cut-out: 9700,1108.48 9700,1068.48 9775,1068.48 9775,1108.48
  pour cut-out: 9575,1208.48 9575,1168.48 9650,1168.48 9650,1208.48
  pour cut-out: 9549.29,1177.21 9549.56,1199.48 9525.44,1199.76 9525.44,1177.6
  pour cut-out: 9523.3,1177.21 9523.57,1199.48 9499.46,1199.76 9499.46,1177.6
  pour cut-out: 9736.27,1718.77 9714,1719.04 9713.73,1694.93 9735.89,1694.93
  pour cut-out: 9736.27,1692.79 9714,1693.06 9713.73,1668.94 9735.89,1668.94
  pour cut-out: 10024.19,2391.22 10008.63,2407.15 9991.39,2390.3 10007.06,2374.63
  pour cut-out: 10042.56,2409.59 10027,2425.53 10009.76,2408.67 10025.43,2393
  pour cut-out: 9524.11,2392.92 9540.05,2408.48 9523.19,2425.72 9507.52,2410.05
  pour cut-out: 9542.48,2374.55 9558.42,2390.1 9541.57,2407.35 9525.89,2391.68
  pour cut-out: 10122.94,1251.49 10138.5,1235.55 10155.74,1252.41 10140.07,1268.08
  pour cut-out: 10104.57,1233.12 10120.13,1217.18 10137.37,1234.04 10121.7,1249.71
  pour cut-out: 10120.51,1059.79 10104.57,1044.23 10121.43,1026.99 10137.1,1042.66
  pour cut-out: 10138.88,1041.41 10122.94,1025.86 10139.8,1008.61 10155.47,1024.29
  pour cut-out: 6218.4,1981.38 6236.08,1981.38 6236.1,1981.4 6236.1,1991.56 6236.08,1991.58 6218.4,1991.58
  pour cut-out: 6218.4,1998.7 6236.08,1998.7 6236.1,1998.72 6236.1,2008.88 6236.08,2008.9 6218.4,2008.9
  pour cut-out: 6219.1,1967.58 6235.28,1967.58 6235.3,1967.59 6235.3,1982.16 6235.28,1982.18 6219.1,1982.18
  pour cut-out: 6219.1,2007.9 6235.28,2007.9 6235.3,2007.92 6235.3,2022.48 6235.28,2022.5 6219.1,2022.5
  pour cut-out: 6238.5,2044.4 6216.23,2044.67 6215.96,2020.56 6238.12,2020.56
  pour cut-out: 6238.5,2070.39 6216.23,2070.66 6215.96,2046.54 6238.12,2046.54
  pour cut-out: 6256.92,1799.88 6241.12,1799.88 6241.11,1799.89 6241.11,1813.68 6241.12,1813.68 6256.9,1813.68 6256.91,1813.69
  pour cut-out: 6232.92,1799.88 6217.12,1799.88 6217.11,1799.89 6217.11,1813.68 6217.12,1813.68 6232.9,1813.68 6232.91,1813.69
  pour cut-out: 6256.92,1776.26 6241.12,1776.26 6241.11,1776.27 6241.11,1790.05 6241.12,1790.06 6256.9,1790.06 6256.91,1790.07
  pour cut-out: 6232.92,1776.26 6217.12,1776.26 6217.11,1776.27 6217.11,1790.05 6217.12,1790.06 6232.9,1790.06 6232.91,1790.07
  pour cut-out: 6258.11,1985.72 6235.84,1985.99 6235.57,1961.88 6257.73,1961.88
  pour cut-out: 6259.27,1968.2 6237,1968.47 6236.72,1944.36 6258.89,1944.36
  pour cut-out: 6259.27,1942.22 6237,1942.49 6236.72,1918.37 6258.89,1918.37
  pour cut-out: 6238.5,1969.28 6216.23,1969.55 6215.96,1945.44 6238.12,1945.44
  pour cut-out: 6238.5,1943.29 6216.23,1943.56 6215.96,1919.45 6238.12,1919.45
  pour cut-out: 6260.19,1775.78 6237.92,1776.05 6237.64,1751.94 6259.81,1751.94
  pour cut-out: 6260.19,1749.79 6237.92,1750.06 6237.64,1725.95 6259.81,1725.95
  pour cut-out: 6236.19,1775.78 6213.92,1776.05 6213.64,1751.94 6235.81,1751.94
  pour cut-out: 6236.19,1749.79 6213.92,1750.06 6213.64,1725.95 6235.81,1725.95
  pour cut-out: 6236.19,1732.77 6213.92,1733.04 6213.64,1708.93 6235.81,1708.93
  pour cut-out: 6236.19,1706.79 6213.92,1707.06 6213.64,1682.94 6235.81,1682.94
  pour cut-out: 6260.19,1732.77 6237.92,1733.04 6237.64,1708.93 6259.81,1708.93
  pour cut-out: 6260.19,1706.79 6237.92,1707.06 6237.64,1682.94 6259.81,1682.94
  pour cut-out: 6261.51,1666.71 6261.78,1688.98 6237.67,1689.26 6237.67,1667.1
  pour cut-out: 6212.35,1689.25 6212.08,1666.98 6236.19,1666.71 6236.19,1688.87
  pour cut-out: 6236.19,1672.77 6213.92,1673.04 6213.64,1648.93 6235.81,1648.93
  pour cut-out: 6236.19,1646.79 6213.92,1647.06 6213.64,1622.94 6235.81,1622.94
  pour cut-out: 6260.19,1672.77 6237.92,1673.04 6237.64,1648.93 6259.81,1648.93
  pour cut-out: 6260.19,1646.79 6237.92,1647.06 6237.64,1622.94 6259.81,1622.94
  pour cut-out: 6260.19,1629.78 6237.92,1630.05 6237.64,1605.94 6259.81,1605.94
  pour cut-out: 6260.19,1603.79 6237.92,1604.06 6237.64,1579.95 6259.81,1579.95
  pour cut-out: 6236.19,1629.78 6213.92,1630.05 6213.64,1605.94 6235.81,1605.94
  pour cut-out: 6236.19,1603.79 6213.92,1604.06 6213.64,1579.95 6235.81,1579.95
  pour cut-out: 6264.79,1104.73 6265.06,1127 6240.95,1127.27 6240.95,1105.11
  pour cut-out: 6232.78,1104.73 6233.05,1127 6208.94,1127.27 6208.94,1105.11
  pour cut-out: 6241.73,1121.22 6264,1120.95 6264.27,1145.06 6242.11,1145.06
  pour cut-out: 6241.73,1147.21 6264,1146.94 6264.27,1171.05 6242.11,1171.05
  pour cut-out: 6209.73,1121.22 6232,1120.95 6232.27,1145.06 6210.11,1145.06
  pour cut-out: 6209.73,1147.21 6232,1146.94 6232.27,1171.05 6210.11,1171.05
  pour cut-out: 6232.27,1110.78 6210,1111.05 6209.73,1086.94 6231.89,1086.94
  pour cut-out: 6232.27,1084.79 6210,1085.06 6209.73,1060.95 6231.89,1060.95
  pour cut-out: 6264.27,1110.78 6242,1111.05 6241.73,1086.94 6263.89,1086.94
  pour cut-out: 6264.27,1084.79 6242,1085.06 6241.73,1060.95 6263.89,1060.95
  pour cut-out: 6241.19,927.27 6240.92,905 6265.03,904.73 6265.03,926.89
  pour cut-out: 6267.17,927.27 6266.9,905 6291.02,904.73 6291.02,926.89
  pour cut-out: 6264.27,927.81 6242,928.08 6241.73,903.97 6263.89,903.97
  pour cut-out: 6264.27,901.83 6242,902.1 6241.73,877.98 6263.89,877.98
  pour cut-out: 6232.27,927.81 6210,928.08 6209.73,903.97 6231.89,903.97
  pour cut-out: 6232.27,901.83 6210,902.1 6209.73,877.98 6231.89,877.98
  pour cut-out: 6183.23,926.29 6182.96,904.02 6207.07,903.75 6207.07,925.91
  pour cut-out: 6209.21,926.29 6208.94,904.02 6233.06,903.75 6233.06,925.91
  pour cut-out: 6175.73,258.25 6198,257.98 6198.27,282.1 6176.11,282.1
  pour cut-out: 6175.73,232.27 6198,232 6198.27,256.11 6176.11,256.11
  pour cut-out: 6215.86,1923 6220,1893 6234,1893 6234,1923
  pour cut-out: 6258.14,1923 6254,1893 6240,1893 6240,1923
  pour cut-out: 6213.92,1802 6220.15,1847.18 6234.15,1847.18 6234.15,1802
  pour cut-out: 6260.38,1802 6254.15,1847.18 6240.15,1847.18 6240.15,1802
  pour cut-out: 6340,1712.1 6340,1675.8 6358,1675.8 6358,1712.1
  pour cut-out: 5708,1253.98 5708,1279 5686,1279 5686,1254.02
  pour cut-out: 5678,1253.98 5678,1279 5656,1279 5656,1254.02
  pour cut-out: 5768.98,1349 5794,1349 5794,1371 5769.02,1371
  pour cut-out: 5768.98,1378 5794,1378 5794,1400 5769.02,1400
  pour cut-out: 6047.99,1356 6084,1356 6084,1372 6048.01,1372
  pour cut-out: 6047.99,1378 6084,1378 6084,1394 6048.01,1394
  pour cut-out: 6026,1393.01 6026,1357 6042,1357 6042,1392.99
  pour cut-out: 6021.01,1369 5985,1369 5985,1351 6020.99,1351
  pour cut-out: 6021.01,1398 5985,1398 5985,1380 6020.99,1380
  pour cut-out: 5979.01,1398 5943,1398 5943,1380 5978.99,1380
  pour cut-out: 5979.01,1369 5943,1369 5943,1351 5978.99,1351
  pour cut-out: 7708.7,2529.05 7708.7,2508.85 7721.3,2508.85 7721.3,2529.05
  pour cut-out: 7708.7,2551.1 7708.7,2530.9 7721.3,2530.9 7721.3,2551.1
  pour cut-out: 7711.7,2628.05 7711.7,2607.85 7724.3,2607.85 7724.3,2628.05
  pour cut-out: 7711.7,2650.1 7711.7,2629.9 7724.3,2629.9 7724.3,2650.1
  pour cut-out: 6558.2,1476.7 6521.8,1476.7 6521.8,1493.3 6558.2,1493.3
  pour cut-out: 7749.01,2492.98 7749.01,2517.16 7806.32,2517.16 7806.32,2492.98
  pour cut-out: 7749.01,2542.98 7749.01,2567.16 7806.32,2567.16 7806.32,2542.98
  pour cut-out: 7749.01,2592.98 7749.01,2617.16 7806.32,2617.16 7806.32,2592.98
  pour cut-out: 7749.01,2642.98 7749.01,2667.16 7806.32,2667.16 7806.32,2642.98
  pour cut-out: 5854.12,2106.95 5854.12,2161.95 5828.12,2161.95 5828.12,2106.95
  pour cut-out: 5880.42,2187.45 5801.82,2187.45 5801.82,2152.15 5880.42,2152.15
  pour cut-out: 5705.85,1984.69 5650.85,1984.69 5650.85,1958.69 5705.85,1958.69
  pour cut-out: 5625.35,2010.99 5625.35,1932.39 5660.65,1932.39 5660.65,2010.99
  pour cut-out: 5814,1173.75 5814,1196.25 5860.2,1196.25 5860.2,1173.75
  pour cut-out: 5860.2,1186.03 5836.8,1186.03 5836.8,1220.15 5860.2,1220.15
  pour cut-out: 5861.22,1154.07 5837.82,1154.07 5837.82,1119.95 5861.22,1119.95
  pour cut-out: 5815.02,1166.35 5815.02,1143.85 5861.22,1143.85 5861.22,1166.35
  pour cut-out: 6558.2,1445.7 6521.8,1445.7 6521.8,1462.3 6558.2,1462.3
  pour cut-out: 6558.2,1413.71 6521.8,1413.71 6521.8,1430.31 6558.2,1430.31
  pour cut-out: 6558.2,1382.71 6521.8,1382.71 6521.8,1399.31 6558.2,1399.31
  pour cut-out: 6558.2,1350.72 6521.8,1350.72 6521.8,1367.32 6558.2,1367.32
  pour cut-out: 6558.2,1319.72 6521.8,1319.72 6521.8,1336.32 6558.2,1336.32
  pour cut-out: 6558.2,1287.72 6521.8,1287.72 6521.8,1304.32 6558.2,1304.32
  pour cut-out: 6558.2,1256.72 6521.8,1256.72 6521.8,1273.32 6558.2,1273.32
  pour cut-out: 6449.8,1153.2 6449.8,1116.8 6433.2,1116.8 6433.2,1153.2
  pour cut-out: 6418.8,1153.2 6418.8,1116.8 6402.2,1116.8 6402.2,1153.2
  pour cut-out: 6386.8,1153.2 6386.8,1116.8 6370.2,1116.8 6370.2,1153.2
  pour cut-out: 6355.8,1153.2 6355.8,1116.8 6339.2,1116.8 6339.2,1153.2
  pour cut-out: 6355.78,1633.2 6355.78,1596.8 6339.18,1596.8 6339.18,1633.2
  pour cut-out: 6386.78,1633.2 6386.78,1596.8 6370.18,1596.8 6370.18,1633.2
  pour cut-out: 6418.77,1633.2 6418.77,1596.8 6402.17,1596.8 6402.17,1633.2
  pour cut-out: 6449.77,1633.2 6449.77,1596.8 6433.17,1596.8 6433.17,1633.2
  text ".Layer_Name" at 579,-854 h60
Layer 7 (PWR/SIGNAL2):
  pour cut-out: 5039,1570.29 5039,1664.29 5038.99,1664.29 ccw(c5015.99,1664.29) 4993,1665 4993,1571 4993.01,1571 ccw(c5016.01,1571)
  pour cut-out: 4680.7,1494.62 4774.7,1494.62 4774.7,1494.63 ccw(c4774.7,1517.63) 4775.41,1540.62 4681.41,1540.62 4681.41,1540.61 ccw(c4681.41,1517.61)
  pour cut-out: 7054.73,1908.41 7148.73,1908.41 7148.73,1908.42 ccw(c7148.73,1931.42) 7149.43,1954.41 7055.43,1954.41 7055.43,1954.4 ccw(c7055.43,1931.4)
  pour cut-out: 7139.32,1996.51 7233.32,1996.51 7233.32,1996.52 ccw(c7233.32,2019.52) 7234.03,2042.51 7140.03,2042.51 7140.03,2042.5 ccw(c7140.03,2019.5)
  pour cut-out: 7191.41,2622.83 7285.41,2622.83 7285.41,2622.84 ccw(c7285.41,2645.84) 7286.12,2668.83 7192.12,2668.83 7192.12,2668.82 ccw(c7192.12,2645.82)
  pour cut-out: 7404.27,2581.67 7498.27,2581.67 7498.27,2581.68 ccw(c7498.27,2604.68) 7498.98,2627.67 7404.98,2627.67 7404.98,2627.66 ccw(c7404.98,2604.66)
  pour cut-out: 6841.58,2329.02 6841.58,2235.02 6841.59,2235.02 ccw(c6864.59,2235.02) 6887.58,2234.32 6887.58,2328.32 6887.57,2328.32 ccw(c6864.57,2328.32)
  pour cut-out: 7081,2708.27 7081,2614.27 7081.01,2614.27 ccw(c7104.01,2614.27) 7127,2613.57 7127,2707.57 7126.99,2707.57 ccw(c7103.99,2707.57)
  pour cut-out: 7466.42,2306.16 7466.42,2212.16 7466.43,2212.16 ccw(c7489.43,2212.16) 7512.42,2211.46 7512.42,2305.46 7512.41,2305.46 ccw(c7489.41,2305.46)
  pour cut-out: 7653,2677.71 7653,2583.71 7653.01,2583.71 ccw(c7676.01,2583.71) 7699,2583 7699,2677 7698.99,2677 ccw(c7675.99,2677)
  pour cut-out: 7537.91,2443.61 7471.45,2377.14 7471.45,2377.13 ccw(c7487.72,2360.87) 7503.47,2344.11 7569.94,2410.58 7569.93,2410.59 ccw(c7553.67,2426.85)
  pour cut-out: 7669.24,2491.76 7602.77,2425.3 7602.78,2425.29 ccw(c7619.04,2409.02) 7634.79,2392.27 7634.8,2392.27 7701.26,2458.74 ccw(c7684.99,2475.01)
  pour cut-out: 5762.2,2254.55 ccw(c5840.92,2254.55) 5840.92,2175.83 ccw(c5840.92,2254.55) 5919.64,2254.55 ccw(c5840.92,2254.55) 5840.92,2333.27 ccw(c5840.92,2254.55)
  pour cut-out: 5558.25,1892.77 ccw(c5558.25,1971.49) 5636.97,1971.49 ccw(c5558.25,1971.49) 5558.25,2050.21 ccw(c5558.25,1971.49) 5479.53,1971.49 ccw(c5558.25,1971.49)
  pour cut-out: 7728,675 7825,675 7825,575 7717.5,575 7717.5,664.5
  pour cut-out: 7275.74,678.38 7725,678.38 7725,175 6975,175 6975,469 7275,469 7275,475
  pour cut-out: 5880.42,2187.45 5801.82,2187.45 5801.82,2152.15 5880.42,2152.15
  pour cut-out: 5625.35,2010.99 5625.35,1932.39 5660.65,1932.39 5660.65,2010.99
  text ".Layer_Name" at 578,-856 h60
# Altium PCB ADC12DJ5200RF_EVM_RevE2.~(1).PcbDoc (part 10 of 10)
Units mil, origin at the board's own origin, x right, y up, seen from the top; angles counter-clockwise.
Board outline 10500 x 2750 mil, 14 copper layers (Top Copper, Layer 2 (GND1), Layer 3 (SIG1), Layer 4 (GND2, Layer 5 (PWR1), Layer 6 (GND3), Layer 7 (PWR/SIGNAL2), Layer 8 (PWR/SIGNAL3), Layer 9 (GND4), Layer 10 PWR2), Layer 11 (GND5), Layer 12 (SIG4), Layer 13 (GND6), Bottom Copper), stack 60.6 mil thick; 701 components, 826 nets, 3386 pads, 2128 vias.

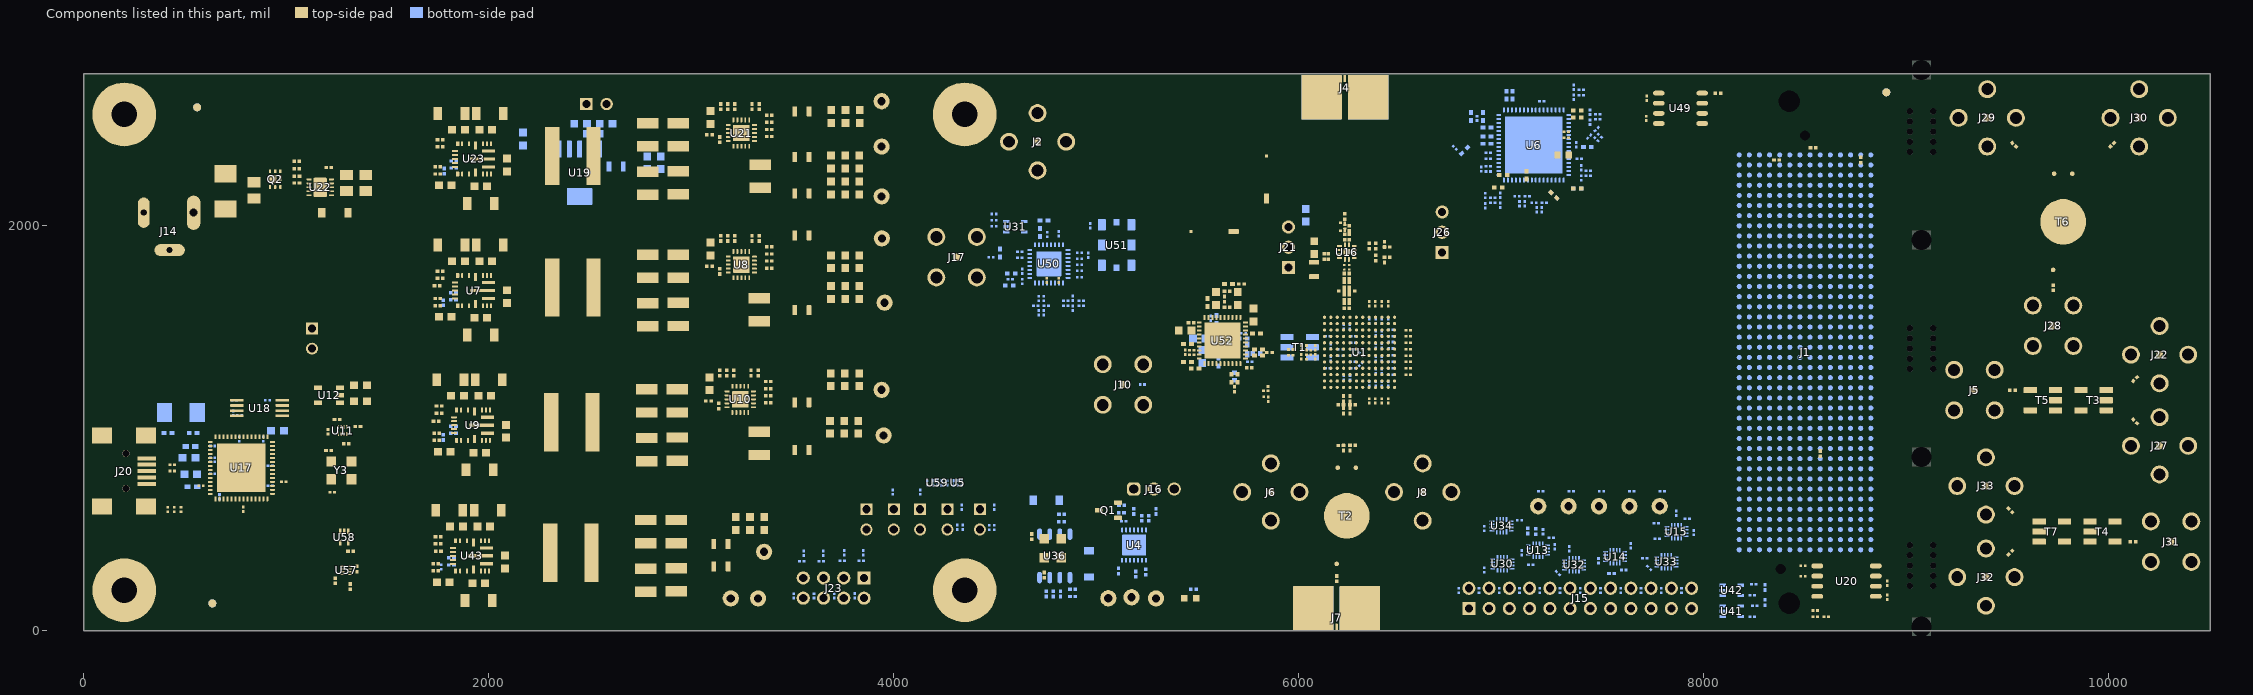
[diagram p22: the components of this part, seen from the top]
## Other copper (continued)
Bottom Copper:
  pour cut-out: 4992.97,1633.82 4992.97,1602.82 4993,1602.82 ccw(c5016,1603) 5038.98,1602.05 5038.99,1602.03 5038.99,1633.03 5038.96,1633.02 ccw(c5015.96,1632.86)
  pour cut-out: 7646.67,2469.24 7624.75,2447.32 7624.77,2447.3 ccw(c7641.16,2431.16) 7656.74,2414.24 7656.73,2414.21 7678.65,2436.14 7678.62,2436.15 ccw(c7662.24,2452.3)
  pour cut-out: 7515.35,2421.08 7493.43,2399.16 7493.45,2399.14 ccw(c7509.84,2383) 7525.41,2366.08 7525.4,2366.06 7547.33,2387.98 7547.3,2388 ccw(c7530.92,2404.15)
  pour cut-out: 6887.61,2265.5 6887.61,2296.5 6887.58,2296.49 ccw(c6864.58,2296.32) 6841.6,2297.27 6841.59,2297.29 6841.59,2266.29 6841.62,2266.29 ccw(c6864.62,2266.46)
  pour cut-out: 7171.21,1996.48 7202.21,1996.48 7202.2,1996.51 ccw(c7202.03,2019.51) 7202.98,2042.49 7203,2042.5 7172,2042.5 7172,2042.47 ccw(c7172.17,2019.47)
  pour cut-out: 4744.23,1540.65 4713.23,1540.65 4713.23,1540.62 ccw(c4713.41,1517.62) 4712.46,1494.64 4712.44,1494.63 4743.44,1494.63 4743.43,1494.66 ccw(c4743.27,1517.67)
  pour cut-out: 7525.54,2366.14 7547.46,2388.06 7547.44,2388.08 ccw(c7531.05,2404.22) 7515.47,2421.14 7515.48,2421.16 7493.56,2399.24 7493.58,2399.22 ccw(c7509.97,2383.07)
  pour cut-out: 7656.86,2414.3 7678.78,2436.22 7678.76,2436.23 ccw(c7662.37,2452.37) 7646.8,2469.3 7646.8,2469.32 7624.88,2447.4 7624.91,2447.38 ccw(c7641.29,2431.23)
  pour cut-out: 7466.4,2274.28 7466.4,2243.28 7466.43,2243.28 ccw(c7489.42,2243.46) 7512.41,2242.5 7512.41,2242.48 7512.41,2273.48 7512.39,2273.48 ccw(c7489.38,2273.31)
  pour cut-out: 7127.03,2644.75 7127.03,2675.75 7127,2675.74 ccw(c7104,2675.57) 7081.02,2676.52 7081.01,2676.54 7081.01,2645.54 7081.04,2645.54 ccw(c7104.04,2645.71)
  pour cut-out: 7436.16,2581.64 7467.16,2581.64 7467.16,2581.67 ccw(c7466.98,2604.67) 7467.93,2627.65 7467.95,2627.66 7436.95,2627.66 7436.96,2627.63 ccw(c7437.12,2604.63)
  pour cut-out: 7223.3,2622.8 7254.3,2622.8 7254.3,2622.83 ccw(c7254.12,2645.83) 7255.07,2668.81 7255.09,2668.82 7224.09,2668.82 7224.1,2668.79 ccw(c7224.26,2645.79)
  pour cut-out: 7086.61,1908.38 7117.61,1908.38 7117.61,1908.41 ccw(c7117.43,1931.41) 7118.39,1954.39 7118.41,1954.4 7087.41,1954.4 7087.41,1954.37 ccw(c7087.58,1931.37)
  pour cut-out: 7699.03,2614.18 7699.03,2645.18 7699,2645.18 ccw(c7676,2645) 7653.02,2645.95 7653.01,2645.97 7653.01,2614.97 7653.04,2614.98 ccw(c7676.04,2615.14)
  pour cut-out: 8809,1850 ccw(c8825,1850) 8841,1850 8841,1900 ccw(c8825,1900) 8809,1900
  pour cut-out: 8759,1750 ccw(c8775,1750) 8791,1750 8791,1800 ccw(c8775,1800) 8759,1800
  pour cut-out: 8809,1650 ccw(c8825,1650) 8841,1650 8841,1700 ccw(c8825,1700) 8809,1700
  pour cut-out: 8759,1550 ccw(c8775,1550) 8791,1550 8791,1600 ccw(c8775,1600) 8759,1600
  pour cut-out: 8809,1450 ccw(c8825,1450) 8841,1450 8841,1500 ccw(c8825,1500) 8809,1500
  pour cut-out: 8659,1950 ccw(c8675,1950) 8691,1950 8691,2000 ccw(c8675,2000) 8659,2000
  pour cut-out: 8659,2150 ccw(c8675,2150) 8691,2150 8691,2200 ccw(c8675,2200) 8659,2200
  pour cut-out: 8809,1250 ccw(c8825,1250) 8841,1250 8841,1300 ccw(c8825,1300) 8809,1300
  region net 3.3V-LMXRF: 5696.2,1263.79 5754.2,1321.79 5754.21,1348.79 5782.21,1348.79 5782.21,1381.79 5734.21,1381.79 5670.21,1317.79 5670.2,1263.79
  pour cut-out: 4969.3,1873.2 4969.3,1836.9 4950.5,1836.9 4950.5,1873.2
  pour cut-out: 4935.29,1827.79 4898.99,1827.79 4898.99,1846.59 4935.29,1846.59
  pour cut-out: 4935.29,1857.79 4898.99,1857.79 4898.99,1876.59 4935.29,1876.59
  pour cut-out: 4943.2,1595.7 4906.9,1595.7 4906.9,1614.5 4943.2,1614.5
  pour cut-out: 4943.2,1620.7 4906.9,1620.7 4906.9,1639.5 4943.2,1639.5
  pour cut-out: 4730.7,1551.8 4730.7,1588.1 4749.5,1588.1 4749.5,1551.8
  pour cut-out: 4705.7,1551.8 4705.7,1588.1 4724.5,1588.1 4724.5,1551.8
  pour cut-out: 6339.46,1509.56 6339.46,1545.96 6356.06,1545.96 6356.06,1509.56
  pour cut-out: 4731.42,1599.72 4751.62,1599.72 4751.62,1612.32 4731.42,1612.32
  pour cut-out: 4702.44,1599.72 4722.64,1599.72 4722.64,1612.32 4702.44,1612.32
  pour cut-out: 4877.68,1613.58 4877.68,1593.38 4890.28,1593.38 4890.28,1613.58
  pour cut-out: 4877.68,1641.54 4877.68,1621.34 4890.28,1621.34 4890.28,1641.54
  pour cut-out: 6988.7,2122.11 6988.7,2101.91 7001.3,2101.91 7001.3,2122.11
  pour cut-out: 4867.18,1595.7 4830.88,1595.7 4830.88,1614.5 4867.18,1614.5
  pour cut-out: 4867.18,1620.7 4830.88,1620.7 4830.88,1639.5 4867.18,1639.5
  pour cut-out: 4730.7,1622.82 4730.7,1659.12 4749.5,1659.12 4749.5,1622.82
  pour cut-out: 4705.7,1622.82 4705.7,1659.12 4724.5,1659.12 4724.5,1622.82
  pour cut-out: 6954.22,2258.7 6917.92,2258.7 6917.92,2277.5 6954.22,2277.5
  pour cut-out: 6954.22,2283.7 6917.92,2283.7 6917.92,2302.5 6954.22,2302.5
  pour cut-out: 7463.34,2446.28 7489.01,2420.62 7475.71,2407.32 7450.05,2432.99
  pour cut-out: 7481.02,2463.96 7506.68,2438.29 7493.39,2425 7467.72,2450.67
  pour cut-out: 7412.39,2635.68 7376.09,2635.68 7376.09,2654.48 7412.39,2654.48
  pour cut-out: 7412.39,2662.68 7376.09,2662.68 7376.09,2681.48 7412.39,2681.48
  pour cut-out: 7494.22,2515.7 7457.92,2515.7 7457.92,2534.5 7494.22,2534.5
  pour cut-out: 7494.22,2540.7 7457.92,2540.7 7457.92,2559.5 7494.22,2559.5
  pour cut-out: 7448.2,2236.72 7411.9,2236.72 7411.9,2255.52 7448.2,2255.52
  pour cut-out: 7448.2,2261.72 7411.9,2261.72 7411.9,2280.52 7448.2,2280.52
  pour cut-out: 7364.49,2634.94 7364.49,2655.14 7351.89,2655.14 7351.89,2634.94
  pour cut-out: 7364.49,2662.89 7364.49,2683.09 7351.89,2683.09 7351.89,2662.89
  pour cut-out: 7388.7,2257.11 7388.7,2236.91 7401.3,2236.91 7401.3,2257.11
  pour cut-out: 7388.7,2285.06 7388.7,2264.86 7401.3,2264.86 7401.3,2285.06
  pour cut-out: 6913.7,2120.63 6913.7,2100.43 6926.3,2100.43 6926.3,2120.63
  pour cut-out: 6913.7,2148.58 6913.7,2128.38 6926.3,2128.38 6926.3,2148.58
  pour cut-out: 6988.7,2150.06 6988.7,2129.86 7001.3,2129.86 7001.3,2150.06
  pour cut-out: 7210.44,2120.23 7190.24,2120.23 7190.24,2107.63 7210.44,2107.64
  pour cut-out: 7182.49,2120.23 7162.29,2120.23 7162.29,2107.63 7182.49,2107.64
  pour cut-out: 7126.54,2151.3 7106.34,2151.3 7106.34,2138.7 7126.54,2138.7
  pour cut-out: 7098.58,2151.3 7078.38,2151.3 7078.38,2138.7 7098.58,2138.7
  pour cut-out: 6976.03,2103.79 6939.73,2103.79 6939.73,2122.59 6976.03,2122.59
  pour cut-out: 6976.03,2128.79 6939.73,2128.79 6939.73,2147.59 6976.03,2147.59
  pour cut-out: 7190.29,2060.73 7190.29,2097.03 7209.09,2097.03 7209.09,2060.73
  pour cut-out: 7165.29,2060.73 7165.29,2097.03 7184.09,2097.03 7184.09,2060.73
  pour cut-out: 7080.7,2090.78 7080.7,2127.08 7099.5,2127.08 7099.5,2090.78
  pour cut-out: 7105.7,2090.78 7105.7,2127.08 7124.5,2127.08 7124.5,2090.78
  pour cut-out: 7444.49,2460.1 7430.2,2445.82 7439.11,2436.91 7453.4,2451.19
  pour cut-out: 7465.72,2481.33 7451.43,2467.05 7460.34,2458.14 7474.63,2472.42
  pour cut-out: 6909.3,2298.2 6909.3,2261.9 6890.5,2261.9 6890.5,2298.2
  pour cut-out: 6371.46,1509.56 6371.46,1545.96 6388.06,1545.96 6388.06,1509.56
  pour cut-out: 6400.96,1509.56 6400.96,1545.96 6417.56,1545.96 6417.56,1509.56
  pour cut-out: 6432.96,1509.56 6432.96,1545.96 6449.56,1545.96 6449.56,1509.56
  pour cut-out: 6340.72,1201.8 6340.72,1238.2 6357.32,1238.2 6357.32,1201.8
  pour cut-out: 6372.72,1201.8 6372.72,1238.2 6389.32,1238.2 6389.32,1201.8
  pour cut-out: 6400.72,1201.8 6400.72,1238.2 6417.32,1238.2 6417.32,1201.8
  pour cut-out: 6432.72,1201.8 6432.72,1238.2 6449.32,1238.2 6449.32,1201.8
  pour cut-out: 6473.2,1477.72 6436.8,1477.72 6436.8,1494.32 6473.2,1494.32
  pour cut-out: 6473.2,1445.72 6436.8,1445.72 6436.8,1462.32 6473.2,1462.32
  pour cut-out: 6473.2,1417.72 6436.8,1417.72 6436.8,1434.32 6473.2,1434.32
  pour cut-out: 6473.2,1385.72 6436.8,1385.72 6436.8,1402.32 6473.2,1402.32
  pour cut-out: 6473.2,1352.72 6436.8,1352.72 6436.8,1369.32 6473.2,1369.32
  pour cut-out: 6473.2,1320.72 6436.8,1320.72 6436.8,1337.32 6473.2,1337.32
  pour cut-out: 6473.2,1287.72 6436.8,1287.72 6436.8,1304.32 6473.2,1304.32
  pour cut-out: 6473.2,1255.72 6436.8,1255.72 6436.8,1272.32 6473.2,1272.32
  pour cut-out: 7444.49,2512.68 7444.49,2532.88 7431.89,2532.88 7431.89,2512.68
  pour cut-out: 7444.49,2540.63 7444.49,2560.83 7431.89,2560.83 7431.89,2540.63
  text ".Layer_Name" at 573,-851 h60
Multi-Layer:
  pour cut-out: 4284,1845 ccw(c4310,1845) 4310,1819 ccw(c4310,1845) 4336,1845 ccw(c4310,1845) 4310,1871 ccw(c4310,1845)
  pour cut-out: 4684,2415 ccw(c4710,2415) 4710,2389 ccw(c4710,2415) 4736,2415 ccw(c4710,2415) 4710,2441 ccw(c4710,2415)
  pour cut-out: 5106,1217 ccw(c5132,1217) 5132,1191 ccw(c5132,1217) 5158,1217 ccw(c5132,1217) 5132,1243 ccw(c5132,1217)
  pour cut-out: 8347,304.49 ccw(c8380,304.49) 8380,271.49 ccw(c8380,304.49) 8413,304.49 ccw(c8380,304.49) 8380,337.49 ccw(c8380,304.49)
  pour cut-out: 8467,2445.49 ccw(c8500,2445.49) 8500,2412.49 ccw(c8500,2445.49) 8533,2445.49 ccw(c8500,2445.49) 8500,2478.49 ccw(c8500,2445.49)
  pour cut-out: 8609,2100 ccw(c8625,2100) 8625,2084 ccw(c8625,2100) 8641,2100 ccw(c8625,2100) 8625,2116 ccw(c8625,2100)
  pour cut-out: 8609,2050 ccw(c8625,2050) 8625,2034 ccw(c8625,2050) 8641,2050 ccw(c8625,2050) 8625,2066 ccw(c8625,2050)
  pour cut-out: 8709,2100 ccw(c8725,2100) 8725,2084 ccw(c8725,2100) 8741,2100 ccw(c8725,2100) 8725,2116 ccw(c8725,2100)
  pour cut-out: 8709,2050 ccw(c8725,2050) 8725,2034 ccw(c8725,2050) 8741,2050 ccw(c8725,2050) 8725,2066 ccw(c8725,2050)
  pour cut-out: 8709,2300 ccw(c8725,2300) 8725,2284 ccw(c8725,2300) 8741,2300 ccw(c8725,2300) 8725,2316 ccw(c8725,2300)
  pour cut-out: 8709,2250 ccw(c8725,2250) 8725,2234 ccw(c8725,2250) 8741,2250 ccw(c8725,2250) 8725,2266 ccw(c8725,2250)
  pour cut-out: 8709,1900 ccw(c8725,1900) 8725,1884 ccw(c8725,1900) 8741,1900 ccw(c8725,1900) 8725,1916 ccw(c8725,1900)
  pour cut-out: 8709,1850 ccw(c8725,1850) 8725,1834 ccw(c8725,1850) 8741,1850 ccw(c8725,1850) 8725,1866 ccw(c8725,1850)
  pour cut-out: 8659,1800 ccw(c8675,1800) 8675,1784 ccw(c8675,1800) 8691,1800 ccw(c8675,1800) 8675,1816 ccw(c8675,1800)
  pour cut-out: 8659,1750 ccw(c8675,1750) 8675,1734 ccw(c8675,1750) 8691,1750 ccw(c8675,1750) 8675,1766 ccw(c8675,1750)
  pour cut-out: 8709,1700 ccw(c8725,1700) 8725,1684 ccw(c8725,1700) 8741,1700 ccw(c8725,1700) 8725,1716 ccw(c8725,1700)
  pour cut-out: 8709,1650 ccw(c8725,1650) 8725,1634 ccw(c8725,1650) 8741,1650 ccw(c8725,1650) 8725,1666 ccw(c8725,1650)
  pour cut-out: 8659,1600 ccw(c8675,1600) 8675,1584 ccw(c8675,1600) 8691,1600 ccw(c8675,1600) 8675,1616 ccw(c8675,1600)
  pour cut-out: 8659,1550 ccw(c8675,1550) 8675,1534 ccw(c8675,1550) 8691,1550 ccw(c8675,1550) 8675,1566 ccw(c8675,1550)
  pour cut-out: 8709,1500 ccw(c8725,1500) 8725,1484 ccw(c8725,1500) 8741,1500 ccw(c8725,1500) 8725,1516 ccw(c8725,1500)
  pour cut-out: 8709,1450 ccw(c8725,1450) 8725,1434 ccw(c8725,1450) 8741,1450 ccw(c8725,1450) 8725,1466 ccw(c8725,1450)
  pour cut-out: 6222,331 6242,331 6242,323 6222,323
  pour cut-out: 6227,812.06 6247,812.06 6247,804.06 6227,804.06
  pour cut-out: 9760,1784 9780,1784 9780,1776 9760,1776
  pour cut-out: 9763.53,2264 9783.53,2264 9783.53,2256 9763.53,2256

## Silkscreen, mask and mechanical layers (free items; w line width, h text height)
Top SilkScreen:
  lines w1: 1852.96,2157 1854,2167 ; 1863,2157 1852,2156 1877,2182
  lines w10: 2595,2481 2622,2508 ; 2622,2100 2622,2508 ; 2649,2481 2622,2508
  text "3.3V" at 4005,2643 h50
  text "CLK" at 4015,2566 h50
  text "AMP / PWR" at 2097,2527 h50
  text "3.3V" at 4008,2444 h50
  text "INA" at 6169.16,2378 h50
  text "TSP" at 5777.77,2368.12 h50
  text "SYS REF" at 4535,2147 h50
  text "LMX" at 4211,2098.02 h50
  text "3.3V" at 4014,2097 h50
  text "TSM" at 5485.74,2078.91 h50
  text "UNINSTALL=5V" at 2232,2057 h35
  text "SCL" at 6777,2048.93 h50
  text "3.3V" at 4001,2013.02 h50
  text "INSTALL=3p3V" at 2232,2005 h35
  text "PWR" at 5748,1971.93 h50
  text "GND" at 6777,1948.93 h50
  text "AMP" at 4011,1948.02 h50
  text "EN" at 5797.98,1871.93 h50
  text "SDA" at 6777,1848.93 h50
  text "GND" at 5748,1771.93 h50
  text "Balun Test / Nov 2020" at 9420,1740 h50 r90
  text "ADC12DJ5200RF EVM" at 90,1717 h105
  text "REV E2" at 965,1635 h100
  text "REF CLK" at 4122,1616 h50
  text "VA11" at 3932,1496 h50
  text "UNINSTALL=USB" at 1192,1474 h35
  text "INSTALL=FMC" at 1197,1378 h35
  text "VA19" at 4023,1161 h50
  text "DEV CLK" at 4970,1005 h50
  text "VDDL19" at 4020,938 h50
  text "CALSTAT" at 7204,679 h40 r90
  text "ORA0" at 7351,679 h40 r90
  text "ORA1" at 7501,679 h40 r90
  text "ORB0" at 7651,679 h40 r90
  text "ORB1" at 7802,679 h40 r90
  text "REFSEL" at 3795,438 h50 r90
  text "ORA0" at 4898,427 h50
  text "VD11" at 3424,423 h50
  text "INBM" at 6583,409 h50
  text "INBP" at 5734,403 h50
  text "SI" at 3970,383 h50
  text "CT" at 4223,383 h50
  text "PD" at 4385,383 h50
  text "SO" at 4094,381 h50
  text "ORB0" at 4897,337 h50
  text "INB" at 5959,234 h50
  text "VBG" at 3144,220 h35
  text "GND" at 3283,219 h35
  text "OT" at 5530,132 h50
  text ".Layer_Name" at 575,-856 h60
Bottom Silk:
  circle w1: c6593.53,2695.28 r32.02
  circle w1: c6705,425 r25
  circle w1: c7145,555 r25
  circle w1: c7543.73,2472.88 r32.02
  circle w1: c8044.23,2701.58 r32.02
  circle w1: c7172.73,1873.48 r32.02
  lines w1: 6110,1290 6110,1345 6125,1345 6125,1390 6145,1390 6145,1435.51 6115.51,1435.51 6115.51,1465 6175,1465 6175,1407.57 6235.28,1407.57 6235.28,1284.72 6240,1280 ; 6240,1460 6240,1470 6245,1470 6300,1470 6300,1460 ; 6260,1220 6260,1210 6205,1210 6205,1280 6240,1280 ; 6265,1180 6320,1180 6321.6,1180 6321.6,970 ; 6270,1280 6270,1180 6160,1180 6160,850 6320,850 ; 6300,1290 6300,1280 6295,1280 6240,1280 ; 6365,1480 6365,1500 6370,1500 6420,1500 6425,1500 6427,1500 6427,1480 ; 6535,400 6580,400 ; 7115,470 7115,530 7210,530 7225,530 7225,480 ; 7124.3,2072.9 7129.8,2085.35 ; 7170,530 7175,530 ; 7174.7,1910.3 7171.7,1910.3 7171.7,1973.4 7129.8,1973.4 7129.8,2085.35 ; 7487.4,2573.2 7766.5,2573.2 ; 7488.3,2466.6 7510,2483.6 ; 7498.8,2482.6 7510,2483.6 ; 7508.8,2473.7 7510,2483.6 ; 7755.7,2582.9 7766.5,2573.2 ; 7920,330 7970,330 7970,540 7950,540 ; 7970,430 8030,430 8030,550 ; 8003.8,2676 8003.8,2559.9 8178.6,2559.9 ; 8020,530 8030,550 ; 8040,530 8030,550 ; 8070.1,2738.8 8281.9,2738.8 ; 8090,950 8090,990 ; 7129.8,2085.35 7134.4,2071.4 7129.8,2085.35 ; 7766.5,2573.2 7757.8,2561.1 7766.5,2573.2 ; 8090,990 8090,1050 7930,1050 7930,950 7730,950 7730,800 7870,800 7870,620 7970,620 7970,550 8090,550 8090,990 ; 6390.9,2537.4 6390.9,2659.8 6609.5,2659.8 6639.9,2659.8 6639.9,2557.8 6576.1,2557.8 6576.1,2468.1 6488.8,2468.1 6488.8,2537.4 6390.9,2537.4 ; 6405,90 6745,90 6745,400 6725,400 6475,400 6465,400 6465,200 6405,200 6405,90
  text "D" at 8054.8,2687.3 h35
  text "E" at 6604.1,2681 h35
  text "INA" at 5715,2545 h50
  text "D" at 7554.3,2458.6 h35
  text "E" at 7183.3,1859.2 h35
  text "A" at 7135,540 h35
  text "A" at 6695,410 h35
  text ".Layer_Name" at 576,-854 h60
Top Paste:
  region: 6344.42,-763.01 6344.81,-763.01 6345.53,-763.31 6346.09,-763.86 6346.39,-764.58 6346.39,-764.97 6346.39,-1149.95 6346.39,-1150.34 6346.09,-1151.06 6345.53,-1151.61 6344.81,-1151.91 6344.42,-1151.91 6171.58,-1151.91 6171.19,-1151.91 6170.47,-1151.61 6169.91,-1151.06 6169.61,-1150.34 6169.61,-1149.95 6169.61,-764.97 6169.61,-764.58 6169.91,-763.86 6170.47,-763.31 6171.19,-763.01 6171.58,-763.01
  text ".Layer_Name" at 581,-857 h60
Bottom Paste:
  text ".Layer_Name" at 573,-854 h60
Top Solder Mask:
  text ".Layer_Name" at 581,-858 h60
Bottom Solder Mask:
  text ".Layer_Name" at 576,-854 h60
M1 Board Outline:
  pour cut-out: 6522.2,353.7
  pour cut-out: 6518.7,356.8
  lines w5: 0,0 10500,0
  lines w10: 0,0 0,2750 10500,2750 10500,0
M2 Board Dimensions:
  text ".Layer_Name" at 3907.48,-846.46 h60
M3 3D STEP Top:
  text ".Layer_Name" at 577,-858.49 h60
M4 3D STEP Bottom:
  text ".Layer_Name" at 577,-858.49 h60
M5 Assembly Top:
  lines w5.91: 6158,-1207.46 6158,-707.46 6358,-707.46 6358,-1207.46 6158,-1207.46
  lines w10: -292,-930.17 6308,-930.17 ; -292,-726.83 6310,-726.83 ; -292,-523.5 -292,-1133.5 3713,-1133.5 6310,-1133.5 6310,-523.5 -291.5,-523.5 -291.5,-1133.5 1284,-1133.5 ; 2173,-1133.5 2173,-523.5 ; 3440,-726.83 3440,-523.5 ; 4280,-726.83 4280,-523.5 ; 4902,-1140 4902,-937.17
  text "COMPONENTS MARKED 'DNP' SHOULD NOT BE POPULATED." at 1153.5,-318.5 h60
  text "ASSEMBLY VARIANT:" at 1153,-434 h60
  text ".VariantName" at 2189,-434 h60
  text "PCB VIEWED FROM TOP SIDE" at -228.5,-655.67 h60
  text "BOARD #:" at 2248,-655.67 h60
  text ".PRJ_Number" at 2793.5,-655.67 h60
  text "REV:" at 3638,-655.67 h60
  text ".PCB_Rev" at 3929.5,-655.67 h60
  text "SVN REV:" at 4476,-655.67 h60
  text ".VersionControl_RevNumber" at 4982,-655.67 h60
  text ".Designator" at 6256.03,-965.99 h19.68 r180
  text "PLOT NAME =" at -228.5,-1064.34 h60
  text "N/A" at 577,-1064.34 h60
  text "TEXAS INSTRUMENTS" at 5113,-1064.34 h60
  text "GENERATED    :" at 2250.58,-1072.83 h60
  text ".Print_Date" at 3120.08,-1072.83 h60
  text ".Print_Time" at 3849.08,-1072.83 h60
M6 Assembly Bottom:
  lines w10: -292.5,-727.33 6309.5,-727.33 ; -290.5,-930.67 6309.5,-930.67 ; 1115.5,-1140.5 1115.5,-937.67 ; 1737.5,-727.33 1737.5,-524 ; 2577.5,-727.33 2577.5,-524 ; 3844.5,-1134 3844.5,-524 ; 4733.5,-1134 6309,-1134 6309,-524 -292.5,-524 -292.5,-1134 2304.5,-1134 6309.5,-1134 6309.5,-524
  text "COMPONENTS MARKED 'DNP' SHOULD NOT BE POPULATED." at 6102,-318 h60
  text ".VariantName" at 5058,-434 h60
  text "ASSEMBLY VARIANT:" at 6097,-434 h60
  text ".VersionControl_RevNumber" at 1180,-650 h60
  text "SVN REV:" at 1541.5,-656.17 h60
  text ".PCB_Rev" at 2088,-656.17 h60
  text "REV:" at 2379.5,-656.17 h60
  text ".PRJ_Number" at 3224,-656.17 h60
  text "BOARD #:" at 3769.5,-656.17 h60
  text "PCB VIEWED FROM BOTTOM SIDE" at 6246,-656.17 h60
  text "TEXAS INSTRUMENTS" at 904.5,-1064.84 h60
  text ".Print_Time" at 2169,-1064.84 h60
  text ".Print_Date" at 2898,-1064.84 h60
  text "GENERATED    :" at 3767.5,-1064.84 h60
  text "N/A" at 5440.5,-1064.84 h60
  text "PLOT NAME =" at 6246,-1064.84 h60
M9 Title Sheet:
  drawing of 57 lines, arcs and shapes, not listed
  text "1" at 739.84,8036.5 h70
  text "2" at 3235.5,8036.5 h70
  text "3" at 5724.84,8036.5 h70
  text "4" at 8231.51,8036.5 h70
  text "5" at 10730.5,8036.5 h70
  text "6" at 13235.5,8036.5 h70
  text "A" at -416.5,6893.5 h70
  text "B" at -416.5,4513.5 h70
  text "B" at 14383.5,4513.5 h70
  text "C" at -416.5,2138.5 h70
  text "C" at 14383.5,2138.5 h70
  text "PROJECT TITLE:" at 11343.5,277.5 h45
  text "ADC12DJ5200RF EVM" at 11393.5,144.17 h70
  text "DESIGNED FOR:" at 11343.5,-23.5 h45
  text "TI" at 11393.5,-163.5 h70
  text "D" at 14383.5,-231.5 h70
  text "FILE NAME:" at 11343.5,-323.5 h45
  text "ADC12DJ5200RF EVM" at 11393.5,-443.5 h70
  text "Texas Instruments (TI) and/or its licensors do not warrant the accuracy or completeness of this specification" at 6374,-605.34 h45
  text "ENGINEER:" at 11343.5,-613.5 h45
  text "LAYOUT BY:" at 12848.5,-613.5 h45
  text "or any information contained therein. TI and/or its licensors do not warrant that this design will meet" at 6329.01,-718 h45
  text ".PRJ_Engineer" at 11393.5,-768.49 h70
  text "BMR" at 12899,-768.49 h70
  text "the specifications, will be suitable for your application or fit for any particular purpose, or will operate in" at 6329.01,-830.67 h45
  text "ALTIUM DESIGNER VERSION:" at 12848.5,-923.5 h45
  text "an implementation. TI and/or its licensors do not warrant that the design is production worthy. You should" at 6329.01,-943.33 h45
  text "completely validate and test your design implementation to confirm the system functionality for your application." at 6374,-1056 h45
  text "print_Scale: 1:1" at 11393.5,-1056.83 h70
  text "305-PD18-0843" at 12899,-1056.83 h70
  text "1" at 739.84,-1263.5 h70
  text "2" at 3235.5,-1263.5 h70
  text "3" at 5724.84,-1263.5 h70
  text "4" at 8231.51,-1263.5 h70
  text "5" at 10730.5,-1263.5 h70
  text "6" at 13235.5,-1263.5 h70
M10 Fab Notes:
  drawing of 226 lines, arcs and shapes, not listed
  text "DESIGN INFORMATION" at 12395.52,7930.98 h60
  text "MIN. TRACK WIDTH:" at 11750.96,7798.85 h60
  text "4" at 12847.2,7798.85 h60
  text "MIL" at 13001.96,7798.85 h60
  text "MIN. CLEARANCE:" at 11750.96,7674.73 h60
  text "MIL" at 13001.96,7674.73 h60
  text "5" at 12847.42,7673.09 h60
  text "MIN. VIA PAD SIZE:" at 11750.96,7550.6 h60
  text "16" at 12817.21,7550.6 h60
  text "MIL" at 13001.96,7550.6 h60
  text "0.05mm (2MIL)" at 12445.96,7420.7 h60
  text "MINIMUM ANNULAR RING" at 11421.73,7412.48 h60
  text "EXTERNAL" at 13153.96,7412.48 h60
  text "PER" at 11621.73,7302.35 h60
  text "IPC-D-275 CLASS 2 LEVEL C" at 11841.73,7302.35 h60
  text "MIL, HOLES" at 13329.96,7201.87 h60
  text "+/-" at 12937.5,7193.29 h60
  text "+/-" at 13791.5,7193.29 h60
  text "REGISTRATION TOLERANCES:" at 11421.73,7192.22 h60
  text "METAL" at 12621.5,7192.22 h60
  text "5" at 13197.7,7192.22 h60
  text "3" at 14030.7,7192.22 h60
  text "MIL" at 14146.96,7192.22 h60
  text "HOLE SIZE TOLERANCE (UNLESS OTHERWISE SPECIFIED):" at 11421.73,7093.91 h60
  text "+/-" at 13791.5,7091.03 h60
  text "3" at 14030.7,7089.97 h60
  text "MIL" at 14146.96,7089.97 h60
  text "MATERIAL:" at 11346.96,6952.32 h60
  text "ISOLA FR4-370HR" at 12333.4,6823.8 h60
  text "FR-408" at 11767.96,6810.15 h60
  text "Isola I-Speed" at 12333.4,6626.95 h60
  text "Meg4" at 11767.96,6614.44 h60
  text "Isola MT-40" at 12333.4,6430.1 h60
  text "Nelco MW-1000" at 13317.65,6430.1 h60
  text "X" at 11634,6425 h60
  text "Meg6" at 11767.96,6417.59 h60
  text "COPPER +PLATING" at 10136,6298.95 h60
  text "OTHER" at 11807.96,6220.74 h60
  text "X" at 11629,6220 h60
  text "Meg6 Equivalent" at 12131.96,6217.59 h60
  text "62 MIL (1.6mm) +/-10%" at 12088.06,6077.71 h60
  text "X" at 11967.96,6075.26 h60
  text "THICKNESS:" at 11421.73,6069.49 h60
  text "OTHER" at 13372.96,6069.49 h60
  text "TOLERANCE:" at 11421.73,5931.17 h60
  text "X" at 12269.96,5931.17 h60
  text "ANSI IPC-6012 TYPE 3 CLASS 2" at 12447.98,5931.17 h60
  text "OTHER +/-" at 12447.96,5786.99 h60
  text "BOW & TWIST:" at 11421.73,5641.8 h60
  text "X" at 12269.96,5641.8 h60
  text "ANSI IPC-6012 TYPE 3 CLASS 2" at 12447.98,5641.8 h60
  text "OTHER +/-" at 12447.96,5495.1 h60
  text "DRILLING:" at 11346.96,5364.48 h60
  text "NC_DRILL FILES" at 13107.96,5259.29 h60
  text "REFERENCE:" at 11421.73,5255.36 h60
  text "X" at 12078.96,5255.26 h60
  text "AS SHOWN" at 12256.96,5255.36 h60
  text "X" at 12979.96,5255.36 h60
  text "OTHER" at 13405.96,5113.1 h60
  text "PTH COPPER THICKNESS:" at 11421.41,5109.57 h60
  text "X" at 12560.64,5109.57 h60
  text "20-30 um" at 12688.64,5109.57 h60
  text "BOARD FINISH:" at 11346.96,4961.98 h60
  text "SILKSCREEN:" at 11502.18,4851.85 h60
  text "X" at 12459.96,4851.85 h60
  text "TOP" at 12576.96,4851.85 h60
  text "X" at 12969.96,4851.85 h60
  text "BOTTOM" at 13087.96,4851.85 h60
  text "SILKSCREEN COLOR:" at 11502.18,4696.66 h60
  text "X" at 12458.96,4696.66 h60
  text "WHITE" at 12576.96,4696.66 h60
  text "OTHER" at 13087.96,4696.66 h60
  text "RED" at 13647.96,4558.21 h60
  text "X" at 13180,4555 h60
  text "GREEN" at 12707.96,4553.21 h60
  text "OTHER" at 13325.96,4553.21 h60
  text "SOLDER RESIST COLOR:" at 11502.18,4546.35 h60
  text "X" at 12589.96,4398.96 h60
  text "MATTE" at 12707.96,4398.96 h60
  text "SEMI-GLOSS" at 13325.5,4398.32 h60
  text "IMMERSION GOLD (ENIG)" at 12407.96,4226.19 h60
  text "ENEPIG" at 13745.5,4218.97 h60
  text "SURFACE FINISH:" at 11346.96,4217.97 h60
  text "X" at 12229.96,4217.97 h60
  text "IMM. TIN/SILVER OR EQUIV" at 11676.5,4080.65 h60
  text "HARD GOLD (30u)" at 13107.96,4076.72 h60
  text "OTHER" at 11701.5,3879.87 h60
  text "ARRAY/PANEL:" at 11346.96,3724.49 h60
  text "CUT AND TRIM PER M1 BOARD OUTLINE" at 12407.96,3716.27 h60
  text "N.C. ROUTE" at 12407.96,3580.3 h60
  text "X" at 13095.96,3580.3 h60
  text "V. SCORE" at 13273.96,3580.3 h60
  text "CERTIFICATION:" at 11346.96,3451.17 h60
  text "MATERIALS AND WORKMANSHIP FOR ALL PCBS" at 12071.96,3451.17 h60
  text "TO MEET OR EXCEED THE REQUIREMENTS OF:" at 12071.96,3357.11 h60
  text "X" at 11709.47,3228.48 h60
  text "ANSI IPC-A-600F CLASS ->" at 11837.46,3228.48 h60
  text "X" at 13485.47,3228.48 h60
  text "2" at 13595.46,3228.48 h60
  text "1" at 13280.46,3226.98 h60
  text "3" at 13949.46,3226.98 h60
  text "COPPER + PLATING" at 10101,3172.95 h60
  text "X" at 12521.47,3080.8 h60
  text "RoHS" at 12649.46,3080.8 h60
  text "OTHER" at 13293.86,3080.8 h60
  text "PER ORDER" at 13690.92,3080.8 h60
  text "ALL BOARDS MUST MEET OR EXCEED UL94-V0 REQUIREMENTS." at 11374.5,2926.97 h60
  text "PCB MUST BEAR THE UL94V-0 UL REGISTERED MATERIAL ID NUMBER" at 11374.5,2810.91 h60
  text "ADDITIONAL REQUIREMENTS:" at 11346.96,2641.48 h60
  text "MICROSECTION:" at 11421.73,2534.36 h60
  text "YES" at 12327.46,2534.36 h60
  text "REQUIRED" at 13188.96,2390.02 h60
  text "BARE BOARD ELEC. TEST:" at 11421.73,2387.17 h60
  text "NONE" at 12727.46,2387.17 h60
  text "X" at 13070.96,2387.17 h60
  text "PER ORDER" at 13780.96,2387.17 h60
  text "X" at 11462.58,2196.71 h60
  text "16 MIL & SMALLER VIAS REQUIRE NON-CONDUCTIVE FILL AND PLANARIZE" at 11573.8,2106.16 h59
  text "X" at 11462.58,1996.71 h60
  text "OUTER LAYER TRACKS 11.5 MIL WIDE REQUIRE 50 OHM SINGLE-ENDED IMPEDANCE" at 11576.75,1895.53 h60
  text "X" at 11462.58,1791.71 h60
  text "OUTER LAYER TRACKS 10.5 MIL WIDE WITH 20.5 MIL SPACE REQUIRE 100 OHM DIFFERENTIAL IMPEDANCE" at 11576.75,1690.8 h60
  text "INNER LAYER XX & XX TRACKS XX MIL WIDE REQUIRE 50 OHM SINGLE-ENDED IMPEDANCE" at 11576.75,1486.08 h60
  text "INNER LAYER 03 & 12 TRACKS 3.25 MIL WIDE WITH   / 8 MIL SPACE REQUIRE 100 OHM DIFFERENTIAL IMPEDANCE" at 11570.85,1292.18 h60
  text "X" at 11462.58,1153.4 h60
  text "NO VENDOR LOGO OR NAME ON THE BOARD" at 11570.85,1133.47 h60
  text "X" at 11462.58,948.68 h60
  text "HOLES LESS THAN 12 MIL ARE DRILL SIZES AND NOT FINISHED HOLE SIZES (FHS)" at 11562.28,871 h60
M11 Gerber Information:
  lines w10: -292,-930.17 6308,-930.17 ; -292,-726.83 6310,-726.83 ; -292,-523.5 -292,-1133.5 3713,-1133.5 6310,-1133.5 6310,-523.5 -291.5,-523.5 -291.5,-1133.5 1284,-1133.5 ; 2173,-1133.5 2173,-523.5 ; 3440,-726.83 3440,-523.5 ; 4280,-726.83 4280,-523.5 ; 4902,-1140 4902,-937.17
  text "BOARD #:" at 2248,-655.67 h60
  text ".PRJ_Number" at 2793.5,-655.67 h60
  text "REV:" at 3638,-655.67 h60
  text ".PCB_Rev" at 3929.5,-655.67 h60
  text "SVN REV:" at 4476,-655.67 h60
  text ".VersionControl_RevNumber" at 4982,-655.67 h60
  text "ALL ARTWORK VIEWED FROM TOP SIDE" at -224,-668 h60
  text "LAYER NAME =" at -228.5,-858.49 h60
  text "PLOT NAME =" at -228.5,-1064.34 h60
  text ".plot_File_Name" at 577,-1064.34 h40
  text "GENERATED    :" at 2250,-1064.34 h60
  text ".Print_Date" at 3119.5,-1064.34 h60
  text ".Print_Time" at 3848.5,-1064.34 h60
  text "TEXAS INSTRUMENTS" at 5113,-1064.34 h60
M12 Stackup:
  drawing of 815 lines, arcs and shapes, not listed
  text "Layer" at 6138.5,6660.5 h60
  text "Name" at 6548.41,6660.5 h60
  text "Material" at 7888.02,6660.5 h60
  text "Thickness" at 8777.78,6660.5 h60
  text "Constant" at 9427.62,6660.5 h60
  text "Board Layer Stack" at 9997.48,6660.5 h60
  text "Top SilkScreen" at 6548.41,6540.5 h60
  text "Top Solder Mask" at 6548.41,6420.5 h60
  text "TAIYO-4000-BN" at 7888.02,6420.5 h60
  text "0.50mil" at 8777.78,6420.5 h60
  text "3.9" at 9427.62,6420.5 h60
  text "1" at 6138.5,6300.5 h60
  text "Top Copper" at 6548.41,6300.5 h60
  text "Copper" at 7888.02,6300.5 h60
  text "2.00mil" at 8777.78,6300.5 h60
  text "Dielectric 1" at 6548.41,6180.5 h60
  text "MEG6-R-5775K" at 7888.02,6180.5 h60
  text "6.00mil" at 8777.78,6180.5 h60
  text "3.42" at 9427.62,6180.5 h60
  text "2" at 6138.5,6060.5 h60
  text "Layer 2 (GND1)" at 6548.41,6060.5 h60
  text "Copper" at 7888.02,6060.5 h60
  text "0.60mil" at 8777.78,6060.5 h60
  text "Dielectric 2" at 6548.41,5940.5 h60
  text "MEG6-R-5670K" at 7888.02,5940.5 h60
  text "3.30mil" at 8777.78,5940.5 h60
  text "3.23" at 9427.62,5940.5 h60
  text "3" at 6138.5,5820.5 h60
  text "Layer 3 (SIG1)" at 6548.41,5820.5 h60
  text "Copper" at 7888.02,5820.5 h60
  text "0.60mil" at 8777.78,5820.5 h60
  text "Dielectric 3" at 6548.41,5700.5 h60
  text "MEG6-R-5775K" at 7888.02,5700.5 h60
  text "3.00mil" at 8777.78,5700.5 h60
  text "3.42" at 9427.62,5700.5 h60
  text "4" at 6138.5,5580.5 h60
  text "Layer 4 (GND2" at 6548.41,5580.5 h60
  text "Copper" at 7888.02,5580.5 h60
  text "0.60mil" at 8777.78,5580.5 h60
  text "Dielectric 4" at 6548.41,5460.5 h60
  text "MEG6-R-5670K" at 7888.02,5460.5 h60
  text "3.50mil" at 8777.78,5460.5 h60
  text "3.23" at 9427.62,5460.5 h60
  text "5" at 6138.5,5340.5 h60
  text "Layer 5 (PWR1)" at 6548.41,5340.5 h60
  text "Copper" at 7888.02,5340.5 h60
  text "1.20mil" at 8777.78,5340.5 h60
  text "Dielectric 5" at 6548.41,5220.5 h60
  text "MEG6-R-5775K" at 7888.02,5220.5 h60
  text "2.60mil" at 8777.78,5220.5 h60
  text "3.58" at 9427.62,5220.5 h60
  text "6" at 6138.5,5100.5 h60
  text "Layer 6 (GND3)" at 6548.41,5100.5 h60
  text "Copper" at 7888.02,5100.5 h60
  text "1.20mil" at 8777.78,5100.5 h60
  text "Dielectric 6" at 6548.41,4980.5 h60
  text "MEG6-R-5670K" at 7888.02,4980.5 h60
  text "3.00mil" at 8777.78,4980.5 h60
  text "3.23" at 9427.62,4980.5 h60
  text "7" at 6138.5,4860.5 h60
  text "Layer 7 (PWR/SIGNAL2)" at 6548.41,4860.5 h60
  text "Copper" at 7888.02,4860.5 h60
  text "1.20mil" at 8777.78,4860.5 h60
  text "Dielectric 7" at 6548.41,4740.5 h60
  text "MEG6-R-5775K" at 7888.02,4740.5 h60
  text "3.00mil" at 8777.78,4740.5 h60
  text "3.42" at 9427.62,4740.5 h60
  text "8" at 6138.5,4620.5 h60
  text "Layer 8 (PWR/SIGNAL3)" at 6548.41,4620.5 h60
  text "Copper" at 7888.02,4620.5 h60
  text "1.20mil" at 8777.78,4620.5 h60
  text "Dielectric 8" at 6548.41,4500.5 h60
  text "MEG6-R-5670K" at 7888.02,4500.5 h60
  text "3.00mil" at 8777.78,4500.5 h60
  text "3.23" at 9427.62,4500.5 h60
  text "9" at 6138.5,4380.5 h60
  text "Layer 9 (GND4)" at 6548.41,4380.5 h60
  text "Copper" at 7888.02,4380.5 h60
  text "1.20mil" at 8777.78,4380.5 h60
  text "Dielectric 9" at 6548.41,4260.5 h60
  text "MEG6-R-5775K" at 7888.02,4260.5 h60
  text "2.60mil" at 8777.78,4260.5 h60
  text "3.58" at 9427.62,4260.5 h60
  text "10" at 6138.5,4140.5 h60
  text "Layer 10 PWR2)" at 6548.41,4140.5 h60
  text "Copper" at 7888.02,4140.5 h60
  text "1.20mil" at 8777.78,4140.5 h60
  text "Dielectric 10" at 6548.41,4020.5 h60
  text "MEG6-R-5670K" at 7888.02,4020.5 h60
  text "3.50mil" at 8777.78,4020.5 h60
  text "3.23" at 9427.62,4020.5 h60
  text "11" at 6138.5,3900.5 h60
  text "Layer 11 (GND5)" at 6548.41,3900.5 h60
  text "Copper" at 7888.02,3900.5 h60
  text "0.60mil" at 8777.78,3900.5 h60
  text "Dielectric 11" at 6548.41,3780.5 h60
  text "MEG6-R-5775K" at 7888.02,3780.5 h60
  text "3.00mil" at 8777.78,3780.5 h60
  text "3.42" at 9427.62,3780.5 h60
  text "12" at 6138.5,3660.5 h60
  text "Layer 12 (SIG4)" at 6548.41,3660.5 h60
  text "Copper" at 7888.02,3660.5 h60
  text "0.60mil" at 8777.78,3660.5 h60
  text "Dielectric 12" at 6548.41,3540.5 h60
  text "MEG6-R-5670K" at 7888.02,3540.5 h60
  text "3.30mil" at 8777.78,3540.5 h60
  text "3.23" at 9427.62,3540.5 h60
  text "13" at 6138.5,3420.5 h60
  text "Layer 13 (GND6)" at 6548.41,3420.5 h60
  text "Copper" at 7888.02,3420.5 h60
  text "0.60mil" at 8777.78,3420.5 h60
  text "Dielectric 13" at 6548.41,3300.5 h60
  text "MEG6-R-5775K" at 7888.02,3300.5 h60
  text "6.00mil" at 8777.78,3300.5 h60
  text "3.42" at 9427.62,3300.5 h60
  text "14" at 6138.5,3180.5 h60
  text "Bottom Copper" at 6548.41,3180.5 h60
  text "Copper" at 7888.02,3180.5 h60
  text "2.00mil" at 8777.78,3180.5 h60
  text "Bottom Solder Mask" at 6548.41,3060.5 h60
  text "TAIYO-4000-BN" at 7888.02,3060.5 h60
  text "0.50mil" at 8777.78,3060.5 h60
  text "3.9" at 9427.62,3060.5 h60
  text "Bottom Silk" at 6548.41,2940.5 h60
  text ".Layer_Name" at 578,-854 h60
M13 Component Bodies Top:
  text ".Layer_Name" at 577,-858.49 h60
M14 Component Bodies Bottom:
  text ".Layer_Name" at 577,-858.49 h60
M15 Courtyards Top:
  text ".Layer_Name" at 577,-858.49 h60
M16 Courtyards Bottom:
  text ".Layer_Name" at 577,-858.49 h60
Drill Drawing:
  drawing of 184 lines, arcs and shapes, not listed
  text "Symbol" at 145.59,6161.3 h72
  text "Quantity" at 446.16,6161.3 h72
  text "Finished Hole Size" at 778.33,6161.3 h72
  text "Plated" at 1414.89,6161.3 h72
  text "Hole Type" at 1674.03,6161.3 h72
  text "Drill Layer Pair" at 2049.19,6161.3 h72
  text "Hole Tolerance" at 2862.76,6161.3 h72
  text "30" at 446.16,6036.98 h60
  text "31.00mil (0.787mm)" at 778.33,6036.98 h60
  text "NPTH" at 1414.89,6036.98 h60
  text "Round" at 1674.03,6036.98 h60
  text "Top Copper - Bottom Copper" at 2049.19,6036.98 h60
  text "+/-3.00mil" at 2862.76,6036.98 h60
  text "E" at 120.31,6026.99 h55.25
  text "2" at 446.16,5912.66 h60
  text "35.43mil (0.900mm)" at 778.33,5912.66 h60
  text "NPTH" at 1414.89,5912.66 h60
  text "Round" at 1674.03,5912.66 h60
  text "Top Copper - Bottom Copper" at 2049.19,5912.66 h60
  text "2" at 446.16,5788.34 h60
  text "50.00mil (1.270mm)" at 778.33,5788.34 h60
  text "NPTH" at 1414.89,5788.34 h60
  text "Round" at 1674.03,5788.34 h60
  text "Top Copper - Bottom Copper" at 2049.19,5788.34 h60
  text "2" at 446.16,5664.02 h60
  text "106.00mil (2.692mm)" at 778.33,5664.02 h60
  text "NPTH" at 1414.89,5664.02 h60
  text "Round" at 1674.03,5664.02 h60
  text "Top Copper - Bottom Copper" at 2049.19,5664.02 h60
  text "131" at 446.16,5539.7 h60
  text "7.87mil (0.200mm)" at 778.33,5539.7 h60
  text "PTH" at 1414.89,5539.7 h60
  text "Round" at 1674.03,5539.7 h60
  text "Top Copper - Bottom Copper" at 2049.19,5539.7 h60
  text "1730" at 446.16,5415.38 h60
  text "8.00mil (0.203mm)" at 778.33,5415.38 h60
  text "PTH" at 1414.89,5415.38 h60
  text "Round" at 1674.03,5415.38 h60
  text "Top Copper - Bottom Copper" at 2049.19,5415.38 h60
  text "2" at 446.16,5291.06 h60
  text "8.00mil (0.203mm)" at 778.33,5291.06 h60
  text "PTH" at 1414.89,5291.06 h60
  text "Round" at 1674.03,5291.06 h60
  text "Top Copper - Bottom Copper" at 2049.19,5291.06 h60
  text "+/-3.00mil" at 2862.76,5291.06 h60
  text "A" at 120.31,5281.07 h55.25
  text "137" at 446.16,5166.74 h60
  text "10.00mil (0.254mm)" at 778.33,5166.74 h60
  text "PTH" at 1414.89,5166.74 h60
  text "Round" at 1674.03,5166.74 h60
  text "Top Copper - Bottom Copper" at 2049.19,5166.74 h60
  text "96" at 446.16,5042.42 h60
  text "10.00mil (0.254mm)" at 778.33,5042.42 h60
  text "PTH" at 1414.89,5042.42 h60
  text "Round" at 1674.03,5042.42 h60
  text "Top Copper - Bottom Copper" at 2049.19,5042.42 h60
  text "+/-3.00mil" at 2862.76,5042.42 h60
  text "B" at 120.31,5032.43 h55.25
  text "12" at 446.16,4918.1 h60
  text "15.00mil (0.381mm)" at 778.33,4918.1 h60
  text "PTH" at 1414.89,4918.1 h60
  text "Round" at 1674.03,4918.1 h60
  text "Top Copper - Bottom Copper" at 2049.19,4918.1 h60
  text "F" at 120.31,4908.11 h55.25
  text "16" at 446.16,4793.78 h60
  text "15.75mil (0.400mm)" at 778.33,4793.78 h60
  text "PTH" at 1414.89,4793.78 h60
  text "Round" at 1674.03,4793.78 h60
  text "Top Copper - Bottom Copper" at 2049.19,4793.78 h60
  text "56" at 446.16,4669.46 h60
  text "40.00mil (1.016mm)" at 778.33,4669.46 h60
  text "PTH" at 1414.89,4669.46 h60
  text "Round" at 1674.03,4669.46 h60
  text "Top Copper - Bottom Copper" at 2049.19,4669.46 h60
  text "14" at 446.16,4545.14 h60
  text "40.16mil (1.020mm)" at 778.33,4545.14 h60
  text "PTH" at 1414.89,4545.14 h60
  text "Round" at 1674.03,4545.14 h60
  text "Top Copper - Bottom Copper" at 2049.19,4545.14 h60
  text "3" at 446.16,4420.82 h60
  text "45.28mil (1.150mm)" at 778.33,4420.82 h60
  text "PTH" at 1414.89,4420.82 h60
  text "Round" at 1674.03,4420.82 h60
  text "Top Copper - Bottom Copper" at 2049.19,4420.82 h60
  text "56" at 446.16,4296.5 h60
  text "59.06mil (1.500mm)" at 778.33,4296.5 h60
  text "PTH" at 1414.89,4296.5 h60
  text "Round" at 1674.03,4296.5 h60
  text "Top Copper - Bottom Copper" at 2049.19,4296.5 h60
  text "4" at 446.16,4172.18 h60
  text "77.95mil (1.980mm)" at 778.33,4172.18 h60
  text "PTH" at 1414.89,4172.18 h60
  text "Round" at 1674.03,4172.18 h60
  text "Top Copper - Bottom Copper" at 2049.19,4172.18 h60
  text "4" at 446.16,4047.86 h60
  text "125.98mil (3.200mm)" at 778.33,4047.86 h60
  text "PTH" at 1414.89,4047.86 h60
  text "Round" at 1674.03,4047.86 h60
  text "Top Copper - Bottom Copper" at 2049.19,4047.86 h60
  text "2" at 446.16,3923.54 h60
  text "100.00mil (2.540mm)" at 778.33,3923.54 h60
  text "NPTH" at 1414.89,3923.54 h60
  text "Slot" at 1674.03,3923.54 h60
  text "Top Copper - Bottom Copper" at 2049.19,3923.54 h60
  text "+/-5.00mil" at 2862.76,3923.54 h60
  text "C" at 120.31,3913.55 h55.25
  text "2" at 446.16,3799.22 h60
  text "100.00mil (2.540mm)" at 778.33,3799.22 h60
  text "NPTH" at 1414.89,3799.22 h60
  text "Slot" at 1674.03,3799.22 h60
  text "Top Copper - Bottom Copper" at 2049.19,3799.22 h60
  text "+/-5.00mil" at 2862.76,3799.22 h60
  text "D" at 120.31,3789.23 h55.25
  text "2" at 446.16,3674.9 h60
  text "29.92mil (0.760mm)" at 778.33,3674.9 h60
  text "PTH" at 1414.89,3674.9 h60
  text "Slot" at 1674.03,3674.9 h60
  text "Top Copper - Bottom Copper" at 2049.19,3674.9 h60
  text "1" at 446.16,3550.58 h60
  text "39.76mil (1.010mm)" at 778.33,3550.58 h60
  text "PTH" at 1414.89,3550.58 h60
  text "Slot" at 1674.03,3550.58 h60
  text "Top Copper - Bottom Copper" at 2049.19,3550.58 h60
  text "2304 Total" at 446.16,3426.26 h60
  text "Slot definitions :" at 145.59,3339.23 h60
  text "Routed Path Length" at 596.31,3339.23 h60
  text "= Calculated from tool start centre position to tool end centre position." at 1136.05,3339.23 h60
  text "Hole Length" at 596.31,3289.51 h60
  text "= Routed Path Length + Tool Size = Slot length as defined in the PCB layout" at 936.24,3289.51 h60
  text ".Layer_Name" at 576,-851 h60

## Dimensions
0,0 to 0,2750 on M2 Board Dimensions
0,0 to 10400,0 on M2 Board Dimensions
